VERSION 5.7 ;
BUSBITCHARS "[]" ;
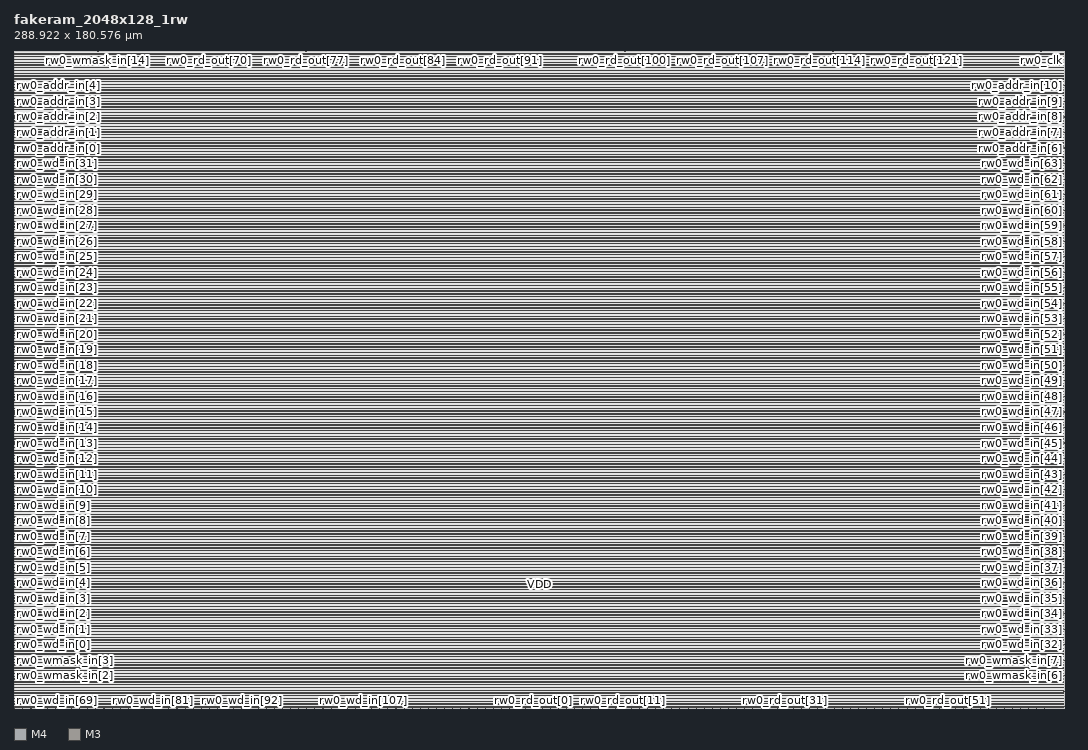
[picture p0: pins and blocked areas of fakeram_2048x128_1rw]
MACRO fakeram_2048x128_1rw
  FOREIGN fakeram_2048x128_1rw 0 0 ;
  SYMMETRY X Y R90 ;
  SIZE 288.922 BY 180.576 ;
  CLASS BLOCK ;
  PIN rw0_wmask_in[0]
    DIRECTION INPUT ;
    USE SIGNAL ;
    SHAPE ABUTMENT ;
    PORT
      LAYER M4 ;
      RECT 0.000 0.276 0.072 0.300 ;
    END
  END rw0_wmask_in[0]
  PIN rw0_wmask_in[1]
    DIRECTION INPUT ;
    USE SIGNAL ;
    SHAPE ABUTMENT ;
    PORT
      LAYER M4 ;
      RECT 0.000 4.548 0.072 4.572 ;
    END
  END rw0_wmask_in[1]
  PIN rw0_wmask_in[2]
    DIRECTION INPUT ;
    USE SIGNAL ;
    SHAPE ABUTMENT ;
    PORT
      LAYER M4 ;
      RECT 0.000 8.820 0.072 8.844 ;
    END
  END rw0_wmask_in[2]
  PIN rw0_wmask_in[3]
    DIRECTION INPUT ;
    USE SIGNAL ;
    SHAPE ABUTMENT ;
    PORT
      LAYER M4 ;
      RECT 0.000 13.092 0.072 13.116 ;
    END
  END rw0_wmask_in[3]
  PIN rw0_wmask_in[4]
    DIRECTION INPUT ;
    USE SIGNAL ;
    SHAPE ABUTMENT ;
    PORT
      LAYER M4 ;
      RECT 288.850 0.276 288.922 0.300 ;
    END
  END rw0_wmask_in[4]
  PIN rw0_wmask_in[5]
    DIRECTION INPUT ;
    USE SIGNAL ;
    SHAPE ABUTMENT ;
    PORT
      LAYER M4 ;
      RECT 288.850 4.548 288.922 4.572 ;
    END
  END rw0_wmask_in[5]
  PIN rw0_wmask_in[6]
    DIRECTION INPUT ;
    USE SIGNAL ;
    SHAPE ABUTMENT ;
    PORT
      LAYER M4 ;
      RECT 288.850 8.820 288.922 8.844 ;
    END
  END rw0_wmask_in[6]
  PIN rw0_wmask_in[7]
    DIRECTION INPUT ;
    USE SIGNAL ;
    SHAPE ABUTMENT ;
    PORT
      LAYER M4 ;
      RECT 288.850 13.092 288.922 13.116 ;
    END
  END rw0_wmask_in[7]
  PIN rw0_wmask_in[8]
    DIRECTION INPUT ;
    USE SIGNAL ;
    SHAPE ABUTMENT ;
    PORT
      LAYER M3 ;
      RECT 0.207 180.522 0.225 180.576 ;
    END
  END rw0_wmask_in[8]
  PIN rw0_wmask_in[9]
    DIRECTION INPUT ;
    USE SIGNAL ;
    SHAPE ABUTMENT ;
    PORT
      LAYER M3 ;
      RECT 4.023 180.522 4.041 180.576 ;
    END
  END rw0_wmask_in[9]
  PIN rw0_wmask_in[10]
    DIRECTION INPUT ;
    USE SIGNAL ;
    SHAPE ABUTMENT ;
    PORT
      LAYER M3 ;
      RECT 7.839 180.522 7.857 180.576 ;
    END
  END rw0_wmask_in[10]
  PIN rw0_wmask_in[11]
    DIRECTION INPUT ;
    USE SIGNAL ;
    SHAPE ABUTMENT ;
    PORT
      LAYER M3 ;
      RECT 11.655 180.522 11.673 180.576 ;
    END
  END rw0_wmask_in[11]
  PIN rw0_wmask_in[12]
    DIRECTION INPUT ;
    USE SIGNAL ;
    SHAPE ABUTMENT ;
    PORT
      LAYER M3 ;
      RECT 15.471 180.522 15.489 180.576 ;
    END
  END rw0_wmask_in[12]
  PIN rw0_wmask_in[13]
    DIRECTION INPUT ;
    USE SIGNAL ;
    SHAPE ABUTMENT ;
    PORT
      LAYER M3 ;
      RECT 19.287 180.522 19.305 180.576 ;
    END
  END rw0_wmask_in[13]
  PIN rw0_wmask_in[14]
    DIRECTION INPUT ;
    USE SIGNAL ;
    SHAPE ABUTMENT ;
    PORT
      LAYER M3 ;
      RECT 23.103 180.522 23.121 180.576 ;
    END
  END rw0_wmask_in[14]
  PIN rw0_wmask_in[15]
    DIRECTION INPUT ;
    USE SIGNAL ;
    SHAPE ABUTMENT ;
    PORT
      LAYER M3 ;
      RECT 26.919 180.522 26.937 180.576 ;
    END
  END rw0_wmask_in[15]
  PIN rw0_wd_in[0]
    DIRECTION INPUT ;
    USE SIGNAL ;
    SHAPE ABUTMENT ;
    PORT
      LAYER M4 ;
      RECT 0.000 17.364 0.072 17.388 ;
    END
  END rw0_wd_in[0]
  PIN rw0_wd_in[1]
    DIRECTION INPUT ;
    USE SIGNAL ;
    SHAPE ABUTMENT ;
    PORT
      LAYER M4 ;
      RECT 0.000 21.636 0.072 21.660 ;
    END
  END rw0_wd_in[1]
  PIN rw0_wd_in[2]
    DIRECTION INPUT ;
    USE SIGNAL ;
    SHAPE ABUTMENT ;
    PORT
      LAYER M4 ;
      RECT 0.000 25.908 0.072 25.932 ;
    END
  END rw0_wd_in[2]
  PIN rw0_wd_in[3]
    DIRECTION INPUT ;
    USE SIGNAL ;
    SHAPE ABUTMENT ;
    PORT
      LAYER M4 ;
      RECT 0.000 30.180 0.072 30.204 ;
    END
  END rw0_wd_in[3]
  PIN rw0_wd_in[4]
    DIRECTION INPUT ;
    USE SIGNAL ;
    SHAPE ABUTMENT ;
    PORT
      LAYER M4 ;
      RECT 0.000 34.452 0.072 34.476 ;
    END
  END rw0_wd_in[4]
  PIN rw0_wd_in[5]
    DIRECTION INPUT ;
    USE SIGNAL ;
    SHAPE ABUTMENT ;
    PORT
      LAYER M4 ;
      RECT 0.000 38.724 0.072 38.748 ;
    END
  END rw0_wd_in[5]
  PIN rw0_wd_in[6]
    DIRECTION INPUT ;
    USE SIGNAL ;
    SHAPE ABUTMENT ;
    PORT
      LAYER M4 ;
      RECT 0.000 42.996 0.072 43.020 ;
    END
  END rw0_wd_in[6]
  PIN rw0_wd_in[7]
    DIRECTION INPUT ;
    USE SIGNAL ;
    SHAPE ABUTMENT ;
    PORT
      LAYER M4 ;
      RECT 0.000 47.268 0.072 47.292 ;
    END
  END rw0_wd_in[7]
  PIN rw0_wd_in[8]
    DIRECTION INPUT ;
    USE SIGNAL ;
    SHAPE ABUTMENT ;
    PORT
      LAYER M4 ;
      RECT 0.000 51.540 0.072 51.564 ;
    END
  END rw0_wd_in[8]
  PIN rw0_wd_in[9]
    DIRECTION INPUT ;
    USE SIGNAL ;
    SHAPE ABUTMENT ;
    PORT
      LAYER M4 ;
      RECT 0.000 55.812 0.072 55.836 ;
    END
  END rw0_wd_in[9]
  PIN rw0_wd_in[10]
    DIRECTION INPUT ;
    USE SIGNAL ;
    SHAPE ABUTMENT ;
    PORT
      LAYER M4 ;
      RECT 0.000 60.084 0.072 60.108 ;
    END
  END rw0_wd_in[10]
  PIN rw0_wd_in[11]
    DIRECTION INPUT ;
    USE SIGNAL ;
    SHAPE ABUTMENT ;
    PORT
      LAYER M4 ;
      RECT 0.000 64.356 0.072 64.380 ;
    END
  END rw0_wd_in[11]
  PIN rw0_wd_in[12]
    DIRECTION INPUT ;
    USE SIGNAL ;
    SHAPE ABUTMENT ;
    PORT
      LAYER M4 ;
      RECT 0.000 68.628 0.072 68.652 ;
    END
  END rw0_wd_in[12]
  PIN rw0_wd_in[13]
    DIRECTION INPUT ;
    USE SIGNAL ;
    SHAPE ABUTMENT ;
    PORT
      LAYER M4 ;
      RECT 0.000 72.900 0.072 72.924 ;
    END
  END rw0_wd_in[13]
  PIN rw0_wd_in[14]
    DIRECTION INPUT ;
    USE SIGNAL ;
    SHAPE ABUTMENT ;
    PORT
      LAYER M4 ;
      RECT 0.000 77.172 0.072 77.196 ;
    END
  END rw0_wd_in[14]
  PIN rw0_wd_in[15]
    DIRECTION INPUT ;
    USE SIGNAL ;
    SHAPE ABUTMENT ;
    PORT
      LAYER M4 ;
      RECT 0.000 81.444 0.072 81.468 ;
    END
  END rw0_wd_in[15]
  PIN rw0_wd_in[16]
    DIRECTION INPUT ;
    USE SIGNAL ;
    SHAPE ABUTMENT ;
    PORT
      LAYER M4 ;
      RECT 0.000 85.716 0.072 85.740 ;
    END
  END rw0_wd_in[16]
  PIN rw0_wd_in[17]
    DIRECTION INPUT ;
    USE SIGNAL ;
    SHAPE ABUTMENT ;
    PORT
      LAYER M4 ;
      RECT 0.000 89.988 0.072 90.012 ;
    END
  END rw0_wd_in[17]
  PIN rw0_wd_in[18]
    DIRECTION INPUT ;
    USE SIGNAL ;
    SHAPE ABUTMENT ;
    PORT
      LAYER M4 ;
      RECT 0.000 94.260 0.072 94.284 ;
    END
  END rw0_wd_in[18]
  PIN rw0_wd_in[19]
    DIRECTION INPUT ;
    USE SIGNAL ;
    SHAPE ABUTMENT ;
    PORT
      LAYER M4 ;
      RECT 0.000 98.532 0.072 98.556 ;
    END
  END rw0_wd_in[19]
  PIN rw0_wd_in[20]
    DIRECTION INPUT ;
    USE SIGNAL ;
    SHAPE ABUTMENT ;
    PORT
      LAYER M4 ;
      RECT 0.000 102.804 0.072 102.828 ;
    END
  END rw0_wd_in[20]
  PIN rw0_wd_in[21]
    DIRECTION INPUT ;
    USE SIGNAL ;
    SHAPE ABUTMENT ;
    PORT
      LAYER M4 ;
      RECT 0.000 107.076 0.072 107.100 ;
    END
  END rw0_wd_in[21]
  PIN rw0_wd_in[22]
    DIRECTION INPUT ;
    USE SIGNAL ;
    SHAPE ABUTMENT ;
    PORT
      LAYER M4 ;
      RECT 0.000 111.348 0.072 111.372 ;
    END
  END rw0_wd_in[22]
  PIN rw0_wd_in[23]
    DIRECTION INPUT ;
    USE SIGNAL ;
    SHAPE ABUTMENT ;
    PORT
      LAYER M4 ;
      RECT 0.000 115.620 0.072 115.644 ;
    END
  END rw0_wd_in[23]
  PIN rw0_wd_in[24]
    DIRECTION INPUT ;
    USE SIGNAL ;
    SHAPE ABUTMENT ;
    PORT
      LAYER M4 ;
      RECT 0.000 119.892 0.072 119.916 ;
    END
  END rw0_wd_in[24]
  PIN rw0_wd_in[25]
    DIRECTION INPUT ;
    USE SIGNAL ;
    SHAPE ABUTMENT ;
    PORT
      LAYER M4 ;
      RECT 0.000 124.164 0.072 124.188 ;
    END
  END rw0_wd_in[25]
  PIN rw0_wd_in[26]
    DIRECTION INPUT ;
    USE SIGNAL ;
    SHAPE ABUTMENT ;
    PORT
      LAYER M4 ;
      RECT 0.000 128.436 0.072 128.460 ;
    END
  END rw0_wd_in[26]
  PIN rw0_wd_in[27]
    DIRECTION INPUT ;
    USE SIGNAL ;
    SHAPE ABUTMENT ;
    PORT
      LAYER M4 ;
      RECT 0.000 132.708 0.072 132.732 ;
    END
  END rw0_wd_in[27]
  PIN rw0_wd_in[28]
    DIRECTION INPUT ;
    USE SIGNAL ;
    SHAPE ABUTMENT ;
    PORT
      LAYER M4 ;
      RECT 0.000 136.980 0.072 137.004 ;
    END
  END rw0_wd_in[28]
  PIN rw0_wd_in[29]
    DIRECTION INPUT ;
    USE SIGNAL ;
    SHAPE ABUTMENT ;
    PORT
      LAYER M4 ;
      RECT 0.000 141.252 0.072 141.276 ;
    END
  END rw0_wd_in[29]
  PIN rw0_wd_in[30]
    DIRECTION INPUT ;
    USE SIGNAL ;
    SHAPE ABUTMENT ;
    PORT
      LAYER M4 ;
      RECT 0.000 145.524 0.072 145.548 ;
    END
  END rw0_wd_in[30]
  PIN rw0_wd_in[31]
    DIRECTION INPUT ;
    USE SIGNAL ;
    SHAPE ABUTMENT ;
    PORT
      LAYER M4 ;
      RECT 0.000 149.796 0.072 149.820 ;
    END
  END rw0_wd_in[31]
  PIN rw0_wd_in[32]
    DIRECTION INPUT ;
    USE SIGNAL ;
    SHAPE ABUTMENT ;
    PORT
      LAYER M4 ;
      RECT 288.850 17.364 288.922 17.388 ;
    END
  END rw0_wd_in[32]
  PIN rw0_wd_in[33]
    DIRECTION INPUT ;
    USE SIGNAL ;
    SHAPE ABUTMENT ;
    PORT
      LAYER M4 ;
      RECT 288.850 21.636 288.922 21.660 ;
    END
  END rw0_wd_in[33]
  PIN rw0_wd_in[34]
    DIRECTION INPUT ;
    USE SIGNAL ;
    SHAPE ABUTMENT ;
    PORT
      LAYER M4 ;
      RECT 288.850 25.908 288.922 25.932 ;
    END
  END rw0_wd_in[34]
  PIN rw0_wd_in[35]
    DIRECTION INPUT ;
    USE SIGNAL ;
    SHAPE ABUTMENT ;
    PORT
      LAYER M4 ;
      RECT 288.850 30.180 288.922 30.204 ;
    END
  END rw0_wd_in[35]
  PIN rw0_wd_in[36]
    DIRECTION INPUT ;
    USE SIGNAL ;
    SHAPE ABUTMENT ;
    PORT
      LAYER M4 ;
      RECT 288.850 34.452 288.922 34.476 ;
    END
  END rw0_wd_in[36]
  PIN rw0_wd_in[37]
    DIRECTION INPUT ;
    USE SIGNAL ;
    SHAPE ABUTMENT ;
    PORT
      LAYER M4 ;
      RECT 288.850 38.724 288.922 38.748 ;
    END
  END rw0_wd_in[37]
  PIN rw0_wd_in[38]
    DIRECTION INPUT ;
    USE SIGNAL ;
    SHAPE ABUTMENT ;
    PORT
      LAYER M4 ;
      RECT 288.850 42.996 288.922 43.020 ;
    END
  END rw0_wd_in[38]
  PIN rw0_wd_in[39]
    DIRECTION INPUT ;
    USE SIGNAL ;
    SHAPE ABUTMENT ;
    PORT
      LAYER M4 ;
      RECT 288.850 47.268 288.922 47.292 ;
    END
  END rw0_wd_in[39]
  PIN rw0_wd_in[40]
    DIRECTION INPUT ;
    USE SIGNAL ;
    SHAPE ABUTMENT ;
    PORT
      LAYER M4 ;
      RECT 288.850 51.540 288.922 51.564 ;
    END
  END rw0_wd_in[40]
  PIN rw0_wd_in[41]
    DIRECTION INPUT ;
    USE SIGNAL ;
    SHAPE ABUTMENT ;
    PORT
      LAYER M4 ;
      RECT 288.850 55.812 288.922 55.836 ;
    END
  END rw0_wd_in[41]
  PIN rw0_wd_in[42]
    DIRECTION INPUT ;
    USE SIGNAL ;
    SHAPE ABUTMENT ;
    PORT
      LAYER M4 ;
      RECT 288.850 60.084 288.922 60.108 ;
    END
  END rw0_wd_in[42]
  PIN rw0_wd_in[43]
    DIRECTION INPUT ;
    USE SIGNAL ;
    SHAPE ABUTMENT ;
    PORT
      LAYER M4 ;
      RECT 288.850 64.356 288.922 64.380 ;
    END
  END rw0_wd_in[43]
  PIN rw0_wd_in[44]
    DIRECTION INPUT ;
    USE SIGNAL ;
    SHAPE ABUTMENT ;
    PORT
      LAYER M4 ;
      RECT 288.850 68.628 288.922 68.652 ;
    END
  END rw0_wd_in[44]
  PIN rw0_wd_in[45]
    DIRECTION INPUT ;
    USE SIGNAL ;
    SHAPE ABUTMENT ;
    PORT
      LAYER M4 ;
      RECT 288.850 72.900 288.922 72.924 ;
    END
  END rw0_wd_in[45]
  PIN rw0_wd_in[46]
    DIRECTION INPUT ;
    USE SIGNAL ;
    SHAPE ABUTMENT ;
    PORT
      LAYER M4 ;
      RECT 288.850 77.172 288.922 77.196 ;
    END
  END rw0_wd_in[46]
  PIN rw0_wd_in[47]
    DIRECTION INPUT ;
    USE SIGNAL ;
    SHAPE ABUTMENT ;
    PORT
      LAYER M4 ;
      RECT 288.850 81.444 288.922 81.468 ;
    END
  END rw0_wd_in[47]
  PIN rw0_wd_in[48]
    DIRECTION INPUT ;
    USE SIGNAL ;
    SHAPE ABUTMENT ;
    PORT
      LAYER M4 ;
      RECT 288.850 85.716 288.922 85.740 ;
    END
  END rw0_wd_in[48]
  PIN rw0_wd_in[49]
    DIRECTION INPUT ;
    USE SIGNAL ;
    SHAPE ABUTMENT ;
    PORT
      LAYER M4 ;
      RECT 288.850 89.988 288.922 90.012 ;
    END
  END rw0_wd_in[49]
  PIN rw0_wd_in[50]
    DIRECTION INPUT ;
    USE SIGNAL ;
    SHAPE ABUTMENT ;
    PORT
      LAYER M4 ;
      RECT 288.850 94.260 288.922 94.284 ;
    END
  END rw0_wd_in[50]
  PIN rw0_wd_in[51]
    DIRECTION INPUT ;
    USE SIGNAL ;
    SHAPE ABUTMENT ;
    PORT
      LAYER M4 ;
      RECT 288.850 98.532 288.922 98.556 ;
    END
  END rw0_wd_in[51]
  PIN rw0_wd_in[52]
    DIRECTION INPUT ;
    USE SIGNAL ;
    SHAPE ABUTMENT ;
    PORT
      LAYER M4 ;
      RECT 288.850 102.804 288.922 102.828 ;
    END
  END rw0_wd_in[52]
  PIN rw0_wd_in[53]
    DIRECTION INPUT ;
    USE SIGNAL ;
    SHAPE ABUTMENT ;
    PORT
      LAYER M4 ;
      RECT 288.850 107.076 288.922 107.100 ;
    END
  END rw0_wd_in[53]
  PIN rw0_wd_in[54]
    DIRECTION INPUT ;
    USE SIGNAL ;
    SHAPE ABUTMENT ;
    PORT
      LAYER M4 ;
      RECT 288.850 111.348 288.922 111.372 ;
    END
  END rw0_wd_in[54]
  PIN rw0_wd_in[55]
    DIRECTION INPUT ;
    USE SIGNAL ;
    SHAPE ABUTMENT ;
    PORT
      LAYER M4 ;
      RECT 288.850 115.620 288.922 115.644 ;
    END
  END rw0_wd_in[55]
  PIN rw0_wd_in[56]
    DIRECTION INPUT ;
    USE SIGNAL ;
    SHAPE ABUTMENT ;
    PORT
      LAYER M4 ;
      RECT 288.850 119.892 288.922 119.916 ;
    END
  END rw0_wd_in[56]
  PIN rw0_wd_in[57]
    DIRECTION INPUT ;
    USE SIGNAL ;
    SHAPE ABUTMENT ;
    PORT
      LAYER M4 ;
      RECT 288.850 124.164 288.922 124.188 ;
    END
  END rw0_wd_in[57]
  PIN rw0_wd_in[58]
    DIRECTION INPUT ;
    USE SIGNAL ;
    SHAPE ABUTMENT ;
    PORT
      LAYER M4 ;
      RECT 288.850 128.436 288.922 128.460 ;
    END
  END rw0_wd_in[58]
  PIN rw0_wd_in[59]
    DIRECTION INPUT ;
    USE SIGNAL ;
    SHAPE ABUTMENT ;
    PORT
      LAYER M4 ;
      RECT 288.850 132.708 288.922 132.732 ;
    END
  END rw0_wd_in[59]
  PIN rw0_wd_in[60]
    DIRECTION INPUT ;
    USE SIGNAL ;
    SHAPE ABUTMENT ;
    PORT
      LAYER M4 ;
      RECT 288.850 136.980 288.922 137.004 ;
    END
  END rw0_wd_in[60]
  PIN rw0_wd_in[61]
    DIRECTION INPUT ;
    USE SIGNAL ;
    SHAPE ABUTMENT ;
    PORT
      LAYER M4 ;
      RECT 288.850 141.252 288.922 141.276 ;
    END
  END rw0_wd_in[61]
  PIN rw0_wd_in[62]
    DIRECTION INPUT ;
    USE SIGNAL ;
    SHAPE ABUTMENT ;
    PORT
      LAYER M4 ;
      RECT 288.850 145.524 288.922 145.548 ;
    END
  END rw0_wd_in[62]
  PIN rw0_wd_in[63]
    DIRECTION INPUT ;
    USE SIGNAL ;
    SHAPE ABUTMENT ;
    PORT
      LAYER M4 ;
      RECT 288.850 149.796 288.922 149.820 ;
    END
  END rw0_wd_in[63]
  PIN rw0_wd_in[64]
    DIRECTION INPUT ;
    USE SIGNAL ;
    SHAPE ABUTMENT ;
    PORT
      LAYER M3 ;
      RECT 0.207 0.000 0.225 0.054 ;
    END
  END rw0_wd_in[64]
  PIN rw0_wd_in[65]
    DIRECTION INPUT ;
    USE SIGNAL ;
    SHAPE ABUTMENT ;
    PORT
      LAYER M3 ;
      RECT 2.439 0.000 2.457 0.054 ;
    END
  END rw0_wd_in[65]
  PIN rw0_wd_in[66]
    DIRECTION INPUT ;
    USE SIGNAL ;
    SHAPE ABUTMENT ;
    PORT
      LAYER M3 ;
      RECT 4.671 0.000 4.689 0.054 ;
    END
  END rw0_wd_in[66]
  PIN rw0_wd_in[67]
    DIRECTION INPUT ;
    USE SIGNAL ;
    SHAPE ABUTMENT ;
    PORT
      LAYER M3 ;
      RECT 6.903 0.000 6.921 0.054 ;
    END
  END rw0_wd_in[67]
  PIN rw0_wd_in[68]
    DIRECTION INPUT ;
    USE SIGNAL ;
    SHAPE ABUTMENT ;
    PORT
      LAYER M3 ;
      RECT 9.135 0.000 9.153 0.054 ;
    END
  END rw0_wd_in[68]
  PIN rw0_wd_in[69]
    DIRECTION INPUT ;
    USE SIGNAL ;
    SHAPE ABUTMENT ;
    PORT
      LAYER M3 ;
      RECT 11.367 0.000 11.385 0.054 ;
    END
  END rw0_wd_in[69]
  PIN rw0_wd_in[70]
    DIRECTION INPUT ;
    USE SIGNAL ;
    SHAPE ABUTMENT ;
    PORT
      LAYER M3 ;
      RECT 13.599 0.000 13.617 0.054 ;
    END
  END rw0_wd_in[70]
  PIN rw0_wd_in[71]
    DIRECTION INPUT ;
    USE SIGNAL ;
    SHAPE ABUTMENT ;
    PORT
      LAYER M3 ;
      RECT 15.831 0.000 15.849 0.054 ;
    END
  END rw0_wd_in[71]
  PIN rw0_wd_in[72]
    DIRECTION INPUT ;
    USE SIGNAL ;
    SHAPE ABUTMENT ;
    PORT
      LAYER M3 ;
      RECT 18.063 0.000 18.081 0.054 ;
    END
  END rw0_wd_in[72]
  PIN rw0_wd_in[73]
    DIRECTION INPUT ;
    USE SIGNAL ;
    SHAPE ABUTMENT ;
    PORT
      LAYER M3 ;
      RECT 20.295 0.000 20.313 0.054 ;
    END
  END rw0_wd_in[73]
  PIN rw0_wd_in[74]
    DIRECTION INPUT ;
    USE SIGNAL ;
    SHAPE ABUTMENT ;
    PORT
      LAYER M3 ;
      RECT 22.527 0.000 22.545 0.054 ;
    END
  END rw0_wd_in[74]
  PIN rw0_wd_in[75]
    DIRECTION INPUT ;
    USE SIGNAL ;
    SHAPE ABUTMENT ;
    PORT
      LAYER M3 ;
      RECT 24.759 0.000 24.777 0.054 ;
    END
  END rw0_wd_in[75]
  PIN rw0_wd_in[76]
    DIRECTION INPUT ;
    USE SIGNAL ;
    SHAPE ABUTMENT ;
    PORT
      LAYER M3 ;
      RECT 26.991 0.000 27.009 0.054 ;
    END
  END rw0_wd_in[76]
  PIN rw0_wd_in[77]
    DIRECTION INPUT ;
    USE SIGNAL ;
    SHAPE ABUTMENT ;
    PORT
      LAYER M3 ;
      RECT 29.223 0.000 29.241 0.054 ;
    END
  END rw0_wd_in[77]
  PIN rw0_wd_in[78]
    DIRECTION INPUT ;
    USE SIGNAL ;
    SHAPE ABUTMENT ;
    PORT
      LAYER M3 ;
      RECT 31.455 0.000 31.473 0.054 ;
    END
  END rw0_wd_in[78]
  PIN rw0_wd_in[79]
    DIRECTION INPUT ;
    USE SIGNAL ;
    SHAPE ABUTMENT ;
    PORT
      LAYER M3 ;
      RECT 33.687 0.000 33.705 0.054 ;
    END
  END rw0_wd_in[79]
  PIN rw0_wd_in[80]
    DIRECTION INPUT ;
    USE SIGNAL ;
    SHAPE ABUTMENT ;
    PORT
      LAYER M3 ;
      RECT 35.919 0.000 35.937 0.054 ;
    END
  END rw0_wd_in[80]
  PIN rw0_wd_in[81]
    DIRECTION INPUT ;
    USE SIGNAL ;
    SHAPE ABUTMENT ;
    PORT
      LAYER M3 ;
      RECT 38.151 0.000 38.169 0.054 ;
    END
  END rw0_wd_in[81]
  PIN rw0_wd_in[82]
    DIRECTION INPUT ;
    USE SIGNAL ;
    SHAPE ABUTMENT ;
    PORT
      LAYER M3 ;
      RECT 40.383 0.000 40.401 0.054 ;
    END
  END rw0_wd_in[82]
  PIN rw0_wd_in[83]
    DIRECTION INPUT ;
    USE SIGNAL ;
    SHAPE ABUTMENT ;
    PORT
      LAYER M3 ;
      RECT 42.615 0.000 42.633 0.054 ;
    END
  END rw0_wd_in[83]
  PIN rw0_wd_in[84]
    DIRECTION INPUT ;
    USE SIGNAL ;
    SHAPE ABUTMENT ;
    PORT
      LAYER M3 ;
      RECT 44.847 0.000 44.865 0.054 ;
    END
  END rw0_wd_in[84]
  PIN rw0_wd_in[85]
    DIRECTION INPUT ;
    USE SIGNAL ;
    SHAPE ABUTMENT ;
    PORT
      LAYER M3 ;
      RECT 47.079 0.000 47.097 0.054 ;
    END
  END rw0_wd_in[85]
  PIN rw0_wd_in[86]
    DIRECTION INPUT ;
    USE SIGNAL ;
    SHAPE ABUTMENT ;
    PORT
      LAYER M3 ;
      RECT 49.311 0.000 49.329 0.054 ;
    END
  END rw0_wd_in[86]
  PIN rw0_wd_in[87]
    DIRECTION INPUT ;
    USE SIGNAL ;
    SHAPE ABUTMENT ;
    PORT
      LAYER M3 ;
      RECT 51.543 0.000 51.561 0.054 ;
    END
  END rw0_wd_in[87]
  PIN rw0_wd_in[88]
    DIRECTION INPUT ;
    USE SIGNAL ;
    SHAPE ABUTMENT ;
    PORT
      LAYER M3 ;
      RECT 53.775 0.000 53.793 0.054 ;
    END
  END rw0_wd_in[88]
  PIN rw0_wd_in[89]
    DIRECTION INPUT ;
    USE SIGNAL ;
    SHAPE ABUTMENT ;
    PORT
      LAYER M3 ;
      RECT 56.007 0.000 56.025 0.054 ;
    END
  END rw0_wd_in[89]
  PIN rw0_wd_in[90]
    DIRECTION INPUT ;
    USE SIGNAL ;
    SHAPE ABUTMENT ;
    PORT
      LAYER M3 ;
      RECT 58.239 0.000 58.257 0.054 ;
    END
  END rw0_wd_in[90]
  PIN rw0_wd_in[91]
    DIRECTION INPUT ;
    USE SIGNAL ;
    SHAPE ABUTMENT ;
    PORT
      LAYER M3 ;
      RECT 60.471 0.000 60.489 0.054 ;
    END
  END rw0_wd_in[91]
  PIN rw0_wd_in[92]
    DIRECTION INPUT ;
    USE SIGNAL ;
    SHAPE ABUTMENT ;
    PORT
      LAYER M3 ;
      RECT 62.703 0.000 62.721 0.054 ;
    END
  END rw0_wd_in[92]
  PIN rw0_wd_in[93]
    DIRECTION INPUT ;
    USE SIGNAL ;
    SHAPE ABUTMENT ;
    PORT
      LAYER M3 ;
      RECT 64.935 0.000 64.953 0.054 ;
    END
  END rw0_wd_in[93]
  PIN rw0_wd_in[94]
    DIRECTION INPUT ;
    USE SIGNAL ;
    SHAPE ABUTMENT ;
    PORT
      LAYER M3 ;
      RECT 67.167 0.000 67.185 0.054 ;
    END
  END rw0_wd_in[94]
  PIN rw0_wd_in[95]
    DIRECTION INPUT ;
    USE SIGNAL ;
    SHAPE ABUTMENT ;
    PORT
      LAYER M3 ;
      RECT 69.399 0.000 69.417 0.054 ;
    END
  END rw0_wd_in[95]
  PIN rw0_wd_in[96]
    DIRECTION INPUT ;
    USE SIGNAL ;
    SHAPE ABUTMENT ;
    PORT
      LAYER M3 ;
      RECT 71.631 0.000 71.649 0.054 ;
    END
  END rw0_wd_in[96]
  PIN rw0_wd_in[97]
    DIRECTION INPUT ;
    USE SIGNAL ;
    SHAPE ABUTMENT ;
    PORT
      LAYER M3 ;
      RECT 73.863 0.000 73.881 0.054 ;
    END
  END rw0_wd_in[97]
  PIN rw0_wd_in[98]
    DIRECTION INPUT ;
    USE SIGNAL ;
    SHAPE ABUTMENT ;
    PORT
      LAYER M3 ;
      RECT 76.095 0.000 76.113 0.054 ;
    END
  END rw0_wd_in[98]
  PIN rw0_wd_in[99]
    DIRECTION INPUT ;
    USE SIGNAL ;
    SHAPE ABUTMENT ;
    PORT
      LAYER M3 ;
      RECT 78.327 0.000 78.345 0.054 ;
    END
  END rw0_wd_in[99]
  PIN rw0_wd_in[100]
    DIRECTION INPUT ;
    USE SIGNAL ;
    SHAPE ABUTMENT ;
    PORT
      LAYER M3 ;
      RECT 80.559 0.000 80.577 0.054 ;
    END
  END rw0_wd_in[100]
  PIN rw0_wd_in[101]
    DIRECTION INPUT ;
    USE SIGNAL ;
    SHAPE ABUTMENT ;
    PORT
      LAYER M3 ;
      RECT 82.791 0.000 82.809 0.054 ;
    END
  END rw0_wd_in[101]
  PIN rw0_wd_in[102]
    DIRECTION INPUT ;
    USE SIGNAL ;
    SHAPE ABUTMENT ;
    PORT
      LAYER M3 ;
      RECT 85.023 0.000 85.041 0.054 ;
    END
  END rw0_wd_in[102]
  PIN rw0_wd_in[103]
    DIRECTION INPUT ;
    USE SIGNAL ;
    SHAPE ABUTMENT ;
    PORT
      LAYER M3 ;
      RECT 87.255 0.000 87.273 0.054 ;
    END
  END rw0_wd_in[103]
  PIN rw0_wd_in[104]
    DIRECTION INPUT ;
    USE SIGNAL ;
    SHAPE ABUTMENT ;
    PORT
      LAYER M3 ;
      RECT 89.487 0.000 89.505 0.054 ;
    END
  END rw0_wd_in[104]
  PIN rw0_wd_in[105]
    DIRECTION INPUT ;
    USE SIGNAL ;
    SHAPE ABUTMENT ;
    PORT
      LAYER M3 ;
      RECT 91.719 0.000 91.737 0.054 ;
    END
  END rw0_wd_in[105]
  PIN rw0_wd_in[106]
    DIRECTION INPUT ;
    USE SIGNAL ;
    SHAPE ABUTMENT ;
    PORT
      LAYER M3 ;
      RECT 93.951 0.000 93.969 0.054 ;
    END
  END rw0_wd_in[106]
  PIN rw0_wd_in[107]
    DIRECTION INPUT ;
    USE SIGNAL ;
    SHAPE ABUTMENT ;
    PORT
      LAYER M3 ;
      RECT 96.183 0.000 96.201 0.054 ;
    END
  END rw0_wd_in[107]
  PIN rw0_wd_in[108]
    DIRECTION INPUT ;
    USE SIGNAL ;
    SHAPE ABUTMENT ;
    PORT
      LAYER M3 ;
      RECT 98.415 0.000 98.433 0.054 ;
    END
  END rw0_wd_in[108]
  PIN rw0_wd_in[109]
    DIRECTION INPUT ;
    USE SIGNAL ;
    SHAPE ABUTMENT ;
    PORT
      LAYER M3 ;
      RECT 100.647 0.000 100.665 0.054 ;
    END
  END rw0_wd_in[109]
  PIN rw0_wd_in[110]
    DIRECTION INPUT ;
    USE SIGNAL ;
    SHAPE ABUTMENT ;
    PORT
      LAYER M3 ;
      RECT 102.879 0.000 102.897 0.054 ;
    END
  END rw0_wd_in[110]
  PIN rw0_wd_in[111]
    DIRECTION INPUT ;
    USE SIGNAL ;
    SHAPE ABUTMENT ;
    PORT
      LAYER M3 ;
      RECT 105.111 0.000 105.129 0.054 ;
    END
  END rw0_wd_in[111]
  PIN rw0_wd_in[112]
    DIRECTION INPUT ;
    USE SIGNAL ;
    SHAPE ABUTMENT ;
    PORT
      LAYER M3 ;
      RECT 107.343 0.000 107.361 0.054 ;
    END
  END rw0_wd_in[112]
  PIN rw0_wd_in[113]
    DIRECTION INPUT ;
    USE SIGNAL ;
    SHAPE ABUTMENT ;
    PORT
      LAYER M3 ;
      RECT 109.575 0.000 109.593 0.054 ;
    END
  END rw0_wd_in[113]
  PIN rw0_wd_in[114]
    DIRECTION INPUT ;
    USE SIGNAL ;
    SHAPE ABUTMENT ;
    PORT
      LAYER M3 ;
      RECT 111.807 0.000 111.825 0.054 ;
    END
  END rw0_wd_in[114]
  PIN rw0_wd_in[115]
    DIRECTION INPUT ;
    USE SIGNAL ;
    SHAPE ABUTMENT ;
    PORT
      LAYER M3 ;
      RECT 114.039 0.000 114.057 0.054 ;
    END
  END rw0_wd_in[115]
  PIN rw0_wd_in[116]
    DIRECTION INPUT ;
    USE SIGNAL ;
    SHAPE ABUTMENT ;
    PORT
      LAYER M3 ;
      RECT 116.271 0.000 116.289 0.054 ;
    END
  END rw0_wd_in[116]
  PIN rw0_wd_in[117]
    DIRECTION INPUT ;
    USE SIGNAL ;
    SHAPE ABUTMENT ;
    PORT
      LAYER M3 ;
      RECT 118.503 0.000 118.521 0.054 ;
    END
  END rw0_wd_in[117]
  PIN rw0_wd_in[118]
    DIRECTION INPUT ;
    USE SIGNAL ;
    SHAPE ABUTMENT ;
    PORT
      LAYER M3 ;
      RECT 120.735 0.000 120.753 0.054 ;
    END
  END rw0_wd_in[118]
  PIN rw0_wd_in[119]
    DIRECTION INPUT ;
    USE SIGNAL ;
    SHAPE ABUTMENT ;
    PORT
      LAYER M3 ;
      RECT 122.967 0.000 122.985 0.054 ;
    END
  END rw0_wd_in[119]
  PIN rw0_wd_in[120]
    DIRECTION INPUT ;
    USE SIGNAL ;
    SHAPE ABUTMENT ;
    PORT
      LAYER M3 ;
      RECT 125.199 0.000 125.217 0.054 ;
    END
  END rw0_wd_in[120]
  PIN rw0_wd_in[121]
    DIRECTION INPUT ;
    USE SIGNAL ;
    SHAPE ABUTMENT ;
    PORT
      LAYER M3 ;
      RECT 127.431 0.000 127.449 0.054 ;
    END
  END rw0_wd_in[121]
  PIN rw0_wd_in[122]
    DIRECTION INPUT ;
    USE SIGNAL ;
    SHAPE ABUTMENT ;
    PORT
      LAYER M3 ;
      RECT 129.663 0.000 129.681 0.054 ;
    END
  END rw0_wd_in[122]
  PIN rw0_wd_in[123]
    DIRECTION INPUT ;
    USE SIGNAL ;
    SHAPE ABUTMENT ;
    PORT
      LAYER M3 ;
      RECT 131.895 0.000 131.913 0.054 ;
    END
  END rw0_wd_in[123]
  PIN rw0_wd_in[124]
    DIRECTION INPUT ;
    USE SIGNAL ;
    SHAPE ABUTMENT ;
    PORT
      LAYER M3 ;
      RECT 134.127 0.000 134.145 0.054 ;
    END
  END rw0_wd_in[124]
  PIN rw0_wd_in[125]
    DIRECTION INPUT ;
    USE SIGNAL ;
    SHAPE ABUTMENT ;
    PORT
      LAYER M3 ;
      RECT 136.359 0.000 136.377 0.054 ;
    END
  END rw0_wd_in[125]
  PIN rw0_wd_in[126]
    DIRECTION INPUT ;
    USE SIGNAL ;
    SHAPE ABUTMENT ;
    PORT
      LAYER M3 ;
      RECT 138.591 0.000 138.609 0.054 ;
    END
  END rw0_wd_in[126]
  PIN rw0_wd_in[127]
    DIRECTION INPUT ;
    USE SIGNAL ;
    SHAPE ABUTMENT ;
    PORT
      LAYER M3 ;
      RECT 140.823 0.000 140.841 0.054 ;
    END
  END rw0_wd_in[127]
  PIN rw0_rd_out[0]
    DIRECTION OUTPUT ;
    USE SIGNAL ;
    SHAPE ABUTMENT ;
    PORT
      LAYER M3 ;
      RECT 143.055 0.000 143.073 0.054 ;
    END
  END rw0_rd_out[0]
  PIN rw0_rd_out[1]
    DIRECTION OUTPUT ;
    USE SIGNAL ;
    SHAPE ABUTMENT ;
    PORT
      LAYER M3 ;
      RECT 145.287 0.000 145.305 0.054 ;
    END
  END rw0_rd_out[1]
  PIN rw0_rd_out[2]
    DIRECTION OUTPUT ;
    USE SIGNAL ;
    SHAPE ABUTMENT ;
    PORT
      LAYER M3 ;
      RECT 147.519 0.000 147.537 0.054 ;
    END
  END rw0_rd_out[2]
  PIN rw0_rd_out[3]
    DIRECTION OUTPUT ;
    USE SIGNAL ;
    SHAPE ABUTMENT ;
    PORT
      LAYER M3 ;
      RECT 149.751 0.000 149.769 0.054 ;
    END
  END rw0_rd_out[3]
  PIN rw0_rd_out[4]
    DIRECTION OUTPUT ;
    USE SIGNAL ;
    SHAPE ABUTMENT ;
    PORT
      LAYER M3 ;
      RECT 151.983 0.000 152.001 0.054 ;
    END
  END rw0_rd_out[4]
  PIN rw0_rd_out[5]
    DIRECTION OUTPUT ;
    USE SIGNAL ;
    SHAPE ABUTMENT ;
    PORT
      LAYER M3 ;
      RECT 154.215 0.000 154.233 0.054 ;
    END
  END rw0_rd_out[5]
  PIN rw0_rd_out[6]
    DIRECTION OUTPUT ;
    USE SIGNAL ;
    SHAPE ABUTMENT ;
    PORT
      LAYER M3 ;
      RECT 156.447 0.000 156.465 0.054 ;
    END
  END rw0_rd_out[6]
  PIN rw0_rd_out[7]
    DIRECTION OUTPUT ;
    USE SIGNAL ;
    SHAPE ABUTMENT ;
    PORT
      LAYER M3 ;
      RECT 158.679 0.000 158.697 0.054 ;
    END
  END rw0_rd_out[7]
  PIN rw0_rd_out[8]
    DIRECTION OUTPUT ;
    USE SIGNAL ;
    SHAPE ABUTMENT ;
    PORT
      LAYER M3 ;
      RECT 160.911 0.000 160.929 0.054 ;
    END
  END rw0_rd_out[8]
  PIN rw0_rd_out[9]
    DIRECTION OUTPUT ;
    USE SIGNAL ;
    SHAPE ABUTMENT ;
    PORT
      LAYER M3 ;
      RECT 163.143 0.000 163.161 0.054 ;
    END
  END rw0_rd_out[9]
  PIN rw0_rd_out[10]
    DIRECTION OUTPUT ;
    USE SIGNAL ;
    SHAPE ABUTMENT ;
    PORT
      LAYER M3 ;
      RECT 165.375 0.000 165.393 0.054 ;
    END
  END rw0_rd_out[10]
  PIN rw0_rd_out[11]
    DIRECTION OUTPUT ;
    USE SIGNAL ;
    SHAPE ABUTMENT ;
    PORT
      LAYER M3 ;
      RECT 167.607 0.000 167.625 0.054 ;
    END
  END rw0_rd_out[11]
  PIN rw0_rd_out[12]
    DIRECTION OUTPUT ;
    USE SIGNAL ;
    SHAPE ABUTMENT ;
    PORT
      LAYER M3 ;
      RECT 169.839 0.000 169.857 0.054 ;
    END
  END rw0_rd_out[12]
  PIN rw0_rd_out[13]
    DIRECTION OUTPUT ;
    USE SIGNAL ;
    SHAPE ABUTMENT ;
    PORT
      LAYER M3 ;
      RECT 172.071 0.000 172.089 0.054 ;
    END
  END rw0_rd_out[13]
  PIN rw0_rd_out[14]
    DIRECTION OUTPUT ;
    USE SIGNAL ;
    SHAPE ABUTMENT ;
    PORT
      LAYER M3 ;
      RECT 174.303 0.000 174.321 0.054 ;
    END
  END rw0_rd_out[14]
  PIN rw0_rd_out[15]
    DIRECTION OUTPUT ;
    USE SIGNAL ;
    SHAPE ABUTMENT ;
    PORT
      LAYER M3 ;
      RECT 176.535 0.000 176.553 0.054 ;
    END
  END rw0_rd_out[15]
  PIN rw0_rd_out[16]
    DIRECTION OUTPUT ;
    USE SIGNAL ;
    SHAPE ABUTMENT ;
    PORT
      LAYER M3 ;
      RECT 178.767 0.000 178.785 0.054 ;
    END
  END rw0_rd_out[16]
  PIN rw0_rd_out[17]
    DIRECTION OUTPUT ;
    USE SIGNAL ;
    SHAPE ABUTMENT ;
    PORT
      LAYER M3 ;
      RECT 180.999 0.000 181.017 0.054 ;
    END
  END rw0_rd_out[17]
  PIN rw0_rd_out[18]
    DIRECTION OUTPUT ;
    USE SIGNAL ;
    SHAPE ABUTMENT ;
    PORT
      LAYER M3 ;
      RECT 183.231 0.000 183.249 0.054 ;
    END
  END rw0_rd_out[18]
  PIN rw0_rd_out[19]
    DIRECTION OUTPUT ;
    USE SIGNAL ;
    SHAPE ABUTMENT ;
    PORT
      LAYER M3 ;
      RECT 185.463 0.000 185.481 0.054 ;
    END
  END rw0_rd_out[19]
  PIN rw0_rd_out[20]
    DIRECTION OUTPUT ;
    USE SIGNAL ;
    SHAPE ABUTMENT ;
    PORT
      LAYER M3 ;
      RECT 187.695 0.000 187.713 0.054 ;
    END
  END rw0_rd_out[20]
  PIN rw0_rd_out[21]
    DIRECTION OUTPUT ;
    USE SIGNAL ;
    SHAPE ABUTMENT ;
    PORT
      LAYER M3 ;
      RECT 189.927 0.000 189.945 0.054 ;
    END
  END rw0_rd_out[21]
  PIN rw0_rd_out[22]
    DIRECTION OUTPUT ;
    USE SIGNAL ;
    SHAPE ABUTMENT ;
    PORT
      LAYER M3 ;
      RECT 192.159 0.000 192.177 0.054 ;
    END
  END rw0_rd_out[22]
  PIN rw0_rd_out[23]
    DIRECTION OUTPUT ;
    USE SIGNAL ;
    SHAPE ABUTMENT ;
    PORT
      LAYER M3 ;
      RECT 194.391 0.000 194.409 0.054 ;
    END
  END rw0_rd_out[23]
  PIN rw0_rd_out[24]
    DIRECTION OUTPUT ;
    USE SIGNAL ;
    SHAPE ABUTMENT ;
    PORT
      LAYER M3 ;
      RECT 196.623 0.000 196.641 0.054 ;
    END
  END rw0_rd_out[24]
  PIN rw0_rd_out[25]
    DIRECTION OUTPUT ;
    USE SIGNAL ;
    SHAPE ABUTMENT ;
    PORT
      LAYER M3 ;
      RECT 198.855 0.000 198.873 0.054 ;
    END
  END rw0_rd_out[25]
  PIN rw0_rd_out[26]
    DIRECTION OUTPUT ;
    USE SIGNAL ;
    SHAPE ABUTMENT ;
    PORT
      LAYER M3 ;
      RECT 201.087 0.000 201.105 0.054 ;
    END
  END rw0_rd_out[26]
  PIN rw0_rd_out[27]
    DIRECTION OUTPUT ;
    USE SIGNAL ;
    SHAPE ABUTMENT ;
    PORT
      LAYER M3 ;
      RECT 203.319 0.000 203.337 0.054 ;
    END
  END rw0_rd_out[27]
  PIN rw0_rd_out[28]
    DIRECTION OUTPUT ;
    USE SIGNAL ;
    SHAPE ABUTMENT ;
    PORT
      LAYER M3 ;
      RECT 205.551 0.000 205.569 0.054 ;
    END
  END rw0_rd_out[28]
  PIN rw0_rd_out[29]
    DIRECTION OUTPUT ;
    USE SIGNAL ;
    SHAPE ABUTMENT ;
    PORT
      LAYER M3 ;
      RECT 207.783 0.000 207.801 0.054 ;
    END
  END rw0_rd_out[29]
  PIN rw0_rd_out[30]
    DIRECTION OUTPUT ;
    USE SIGNAL ;
    SHAPE ABUTMENT ;
    PORT
      LAYER M3 ;
      RECT 210.015 0.000 210.033 0.054 ;
    END
  END rw0_rd_out[30]
  PIN rw0_rd_out[31]
    DIRECTION OUTPUT ;
    USE SIGNAL ;
    SHAPE ABUTMENT ;
    PORT
      LAYER M3 ;
      RECT 212.247 0.000 212.265 0.054 ;
    END
  END rw0_rd_out[31]
  PIN rw0_rd_out[32]
    DIRECTION OUTPUT ;
    USE SIGNAL ;
    SHAPE ABUTMENT ;
    PORT
      LAYER M3 ;
      RECT 214.479 0.000 214.497 0.054 ;
    END
  END rw0_rd_out[32]
  PIN rw0_rd_out[33]
    DIRECTION OUTPUT ;
    USE SIGNAL ;
    SHAPE ABUTMENT ;
    PORT
      LAYER M3 ;
      RECT 216.711 0.000 216.729 0.054 ;
    END
  END rw0_rd_out[33]
  PIN rw0_rd_out[34]
    DIRECTION OUTPUT ;
    USE SIGNAL ;
    SHAPE ABUTMENT ;
    PORT
      LAYER M3 ;
      RECT 218.943 0.000 218.961 0.054 ;
    END
  END rw0_rd_out[34]
  PIN rw0_rd_out[35]
    DIRECTION OUTPUT ;
    USE SIGNAL ;
    SHAPE ABUTMENT ;
    PORT
      LAYER M3 ;
      RECT 221.175 0.000 221.193 0.054 ;
    END
  END rw0_rd_out[35]
  PIN rw0_rd_out[36]
    DIRECTION OUTPUT ;
    USE SIGNAL ;
    SHAPE ABUTMENT ;
    PORT
      LAYER M3 ;
      RECT 223.407 0.000 223.425 0.054 ;
    END
  END rw0_rd_out[36]
  PIN rw0_rd_out[37]
    DIRECTION OUTPUT ;
    USE SIGNAL ;
    SHAPE ABUTMENT ;
    PORT
      LAYER M3 ;
      RECT 225.639 0.000 225.657 0.054 ;
    END
  END rw0_rd_out[37]
  PIN rw0_rd_out[38]
    DIRECTION OUTPUT ;
    USE SIGNAL ;
    SHAPE ABUTMENT ;
    PORT
      LAYER M3 ;
      RECT 227.871 0.000 227.889 0.054 ;
    END
  END rw0_rd_out[38]
  PIN rw0_rd_out[39]
    DIRECTION OUTPUT ;
    USE SIGNAL ;
    SHAPE ABUTMENT ;
    PORT
      LAYER M3 ;
      RECT 230.103 0.000 230.121 0.054 ;
    END
  END rw0_rd_out[39]
  PIN rw0_rd_out[40]
    DIRECTION OUTPUT ;
    USE SIGNAL ;
    SHAPE ABUTMENT ;
    PORT
      LAYER M3 ;
      RECT 232.335 0.000 232.353 0.054 ;
    END
  END rw0_rd_out[40]
  PIN rw0_rd_out[41]
    DIRECTION OUTPUT ;
    USE SIGNAL ;
    SHAPE ABUTMENT ;
    PORT
      LAYER M3 ;
      RECT 234.567 0.000 234.585 0.054 ;
    END
  END rw0_rd_out[41]
  PIN rw0_rd_out[42]
    DIRECTION OUTPUT ;
    USE SIGNAL ;
    SHAPE ABUTMENT ;
    PORT
      LAYER M3 ;
      RECT 236.799 0.000 236.817 0.054 ;
    END
  END rw0_rd_out[42]
  PIN rw0_rd_out[43]
    DIRECTION OUTPUT ;
    USE SIGNAL ;
    SHAPE ABUTMENT ;
    PORT
      LAYER M3 ;
      RECT 239.031 0.000 239.049 0.054 ;
    END
  END rw0_rd_out[43]
  PIN rw0_rd_out[44]
    DIRECTION OUTPUT ;
    USE SIGNAL ;
    SHAPE ABUTMENT ;
    PORT
      LAYER M3 ;
      RECT 241.263 0.000 241.281 0.054 ;
    END
  END rw0_rd_out[44]
  PIN rw0_rd_out[45]
    DIRECTION OUTPUT ;
    USE SIGNAL ;
    SHAPE ABUTMENT ;
    PORT
      LAYER M3 ;
      RECT 243.495 0.000 243.513 0.054 ;
    END
  END rw0_rd_out[45]
  PIN rw0_rd_out[46]
    DIRECTION OUTPUT ;
    USE SIGNAL ;
    SHAPE ABUTMENT ;
    PORT
      LAYER M3 ;
      RECT 245.727 0.000 245.745 0.054 ;
    END
  END rw0_rd_out[46]
  PIN rw0_rd_out[47]
    DIRECTION OUTPUT ;
    USE SIGNAL ;
    SHAPE ABUTMENT ;
    PORT
      LAYER M3 ;
      RECT 247.959 0.000 247.977 0.054 ;
    END
  END rw0_rd_out[47]
  PIN rw0_rd_out[48]
    DIRECTION OUTPUT ;
    USE SIGNAL ;
    SHAPE ABUTMENT ;
    PORT
      LAYER M3 ;
      RECT 250.191 0.000 250.209 0.054 ;
    END
  END rw0_rd_out[48]
  PIN rw0_rd_out[49]
    DIRECTION OUTPUT ;
    USE SIGNAL ;
    SHAPE ABUTMENT ;
    PORT
      LAYER M3 ;
      RECT 252.423 0.000 252.441 0.054 ;
    END
  END rw0_rd_out[49]
  PIN rw0_rd_out[50]
    DIRECTION OUTPUT ;
    USE SIGNAL ;
    SHAPE ABUTMENT ;
    PORT
      LAYER M3 ;
      RECT 254.655 0.000 254.673 0.054 ;
    END
  END rw0_rd_out[50]
  PIN rw0_rd_out[51]
    DIRECTION OUTPUT ;
    USE SIGNAL ;
    SHAPE ABUTMENT ;
    PORT
      LAYER M3 ;
      RECT 256.887 0.000 256.905 0.054 ;
    END
  END rw0_rd_out[51]
  PIN rw0_rd_out[52]
    DIRECTION OUTPUT ;
    USE SIGNAL ;
    SHAPE ABUTMENT ;
    PORT
      LAYER M3 ;
      RECT 259.119 0.000 259.137 0.054 ;
    END
  END rw0_rd_out[52]
  PIN rw0_rd_out[53]
    DIRECTION OUTPUT ;
    USE SIGNAL ;
    SHAPE ABUTMENT ;
    PORT
      LAYER M3 ;
      RECT 261.351 0.000 261.369 0.054 ;
    END
  END rw0_rd_out[53]
  PIN rw0_rd_out[54]
    DIRECTION OUTPUT ;
    USE SIGNAL ;
    SHAPE ABUTMENT ;
    PORT
      LAYER M3 ;
      RECT 263.583 0.000 263.601 0.054 ;
    END
  END rw0_rd_out[54]
  PIN rw0_rd_out[55]
    DIRECTION OUTPUT ;
    USE SIGNAL ;
    SHAPE ABUTMENT ;
    PORT
      LAYER M3 ;
      RECT 265.815 0.000 265.833 0.054 ;
    END
  END rw0_rd_out[55]
  PIN rw0_rd_out[56]
    DIRECTION OUTPUT ;
    USE SIGNAL ;
    SHAPE ABUTMENT ;
    PORT
      LAYER M3 ;
      RECT 268.047 0.000 268.065 0.054 ;
    END
  END rw0_rd_out[56]
  PIN rw0_rd_out[57]
    DIRECTION OUTPUT ;
    USE SIGNAL ;
    SHAPE ABUTMENT ;
    PORT
      LAYER M3 ;
      RECT 270.279 0.000 270.297 0.054 ;
    END
  END rw0_rd_out[57]
  PIN rw0_rd_out[58]
    DIRECTION OUTPUT ;
    USE SIGNAL ;
    SHAPE ABUTMENT ;
    PORT
      LAYER M3 ;
      RECT 272.511 0.000 272.529 0.054 ;
    END
  END rw0_rd_out[58]
  PIN rw0_rd_out[59]
    DIRECTION OUTPUT ;
    USE SIGNAL ;
    SHAPE ABUTMENT ;
    PORT
      LAYER M3 ;
      RECT 274.743 0.000 274.761 0.054 ;
    END
  END rw0_rd_out[59]
  PIN rw0_rd_out[60]
    DIRECTION OUTPUT ;
    USE SIGNAL ;
    SHAPE ABUTMENT ;
    PORT
      LAYER M3 ;
      RECT 276.975 0.000 276.993 0.054 ;
    END
  END rw0_rd_out[60]
  PIN rw0_rd_out[61]
    DIRECTION OUTPUT ;
    USE SIGNAL ;
    SHAPE ABUTMENT ;
    PORT
      LAYER M3 ;
      RECT 279.207 0.000 279.225 0.054 ;
    END
  END rw0_rd_out[61]
  PIN rw0_rd_out[62]
    DIRECTION OUTPUT ;
    USE SIGNAL ;
    SHAPE ABUTMENT ;
    PORT
      LAYER M3 ;
      RECT 281.439 0.000 281.457 0.054 ;
    END
  END rw0_rd_out[62]
  PIN rw0_rd_out[63]
    DIRECTION OUTPUT ;
    USE SIGNAL ;
    SHAPE ABUTMENT ;
    PORT
      LAYER M3 ;
      RECT 283.671 0.000 283.689 0.054 ;
    END
  END rw0_rd_out[63]
  PIN rw0_rd_out[64]
    DIRECTION OUTPUT ;
    USE SIGNAL ;
    SHAPE ABUTMENT ;
    PORT
      LAYER M3 ;
      RECT 30.735 180.522 30.753 180.576 ;
    END
  END rw0_rd_out[64]
  PIN rw0_rd_out[65]
    DIRECTION OUTPUT ;
    USE SIGNAL ;
    SHAPE ABUTMENT ;
    PORT
      LAYER M3 ;
      RECT 34.551 180.522 34.569 180.576 ;
    END
  END rw0_rd_out[65]
  PIN rw0_rd_out[66]
    DIRECTION OUTPUT ;
    USE SIGNAL ;
    SHAPE ABUTMENT ;
    PORT
      LAYER M3 ;
      RECT 38.367 180.522 38.385 180.576 ;
    END
  END rw0_rd_out[66]
  PIN rw0_rd_out[67]
    DIRECTION OUTPUT ;
    USE SIGNAL ;
    SHAPE ABUTMENT ;
    PORT
      LAYER M3 ;
      RECT 42.183 180.522 42.201 180.576 ;
    END
  END rw0_rd_out[67]
  PIN rw0_rd_out[68]
    DIRECTION OUTPUT ;
    USE SIGNAL ;
    SHAPE ABUTMENT ;
    PORT
      LAYER M3 ;
      RECT 45.999 180.522 46.017 180.576 ;
    END
  END rw0_rd_out[68]
  PIN rw0_rd_out[69]
    DIRECTION OUTPUT ;
    USE SIGNAL ;
    SHAPE ABUTMENT ;
    PORT
      LAYER M3 ;
      RECT 49.815 180.522 49.833 180.576 ;
    END
  END rw0_rd_out[69]
  PIN rw0_rd_out[70]
    DIRECTION OUTPUT ;
    USE SIGNAL ;
    SHAPE ABUTMENT ;
    PORT
      LAYER M3 ;
      RECT 53.631 180.522 53.649 180.576 ;
    END
  END rw0_rd_out[70]
  PIN rw0_rd_out[71]
    DIRECTION OUTPUT ;
    USE SIGNAL ;
    SHAPE ABUTMENT ;
    PORT
      LAYER M3 ;
      RECT 57.447 180.522 57.465 180.576 ;
    END
  END rw0_rd_out[71]
  PIN rw0_rd_out[72]
    DIRECTION OUTPUT ;
    USE SIGNAL ;
    SHAPE ABUTMENT ;
    PORT
      LAYER M3 ;
      RECT 61.263 180.522 61.281 180.576 ;
    END
  END rw0_rd_out[72]
  PIN rw0_rd_out[73]
    DIRECTION OUTPUT ;
    USE SIGNAL ;
    SHAPE ABUTMENT ;
    PORT
      LAYER M3 ;
      RECT 65.079 180.522 65.097 180.576 ;
    END
  END rw0_rd_out[73]
  PIN rw0_rd_out[74]
    DIRECTION OUTPUT ;
    USE SIGNAL ;
    SHAPE ABUTMENT ;
    PORT
      LAYER M3 ;
      RECT 68.895 180.522 68.913 180.576 ;
    END
  END rw0_rd_out[74]
  PIN rw0_rd_out[75]
    DIRECTION OUTPUT ;
    USE SIGNAL ;
    SHAPE ABUTMENT ;
    PORT
      LAYER M3 ;
      RECT 72.711 180.522 72.729 180.576 ;
    END
  END rw0_rd_out[75]
  PIN rw0_rd_out[76]
    DIRECTION OUTPUT ;
    USE SIGNAL ;
    SHAPE ABUTMENT ;
    PORT
      LAYER M3 ;
      RECT 76.527 180.522 76.545 180.576 ;
    END
  END rw0_rd_out[76]
  PIN rw0_rd_out[77]
    DIRECTION OUTPUT ;
    USE SIGNAL ;
    SHAPE ABUTMENT ;
    PORT
      LAYER M3 ;
      RECT 80.343 180.522 80.361 180.576 ;
    END
  END rw0_rd_out[77]
  PIN rw0_rd_out[78]
    DIRECTION OUTPUT ;
    USE SIGNAL ;
    SHAPE ABUTMENT ;
    PORT
      LAYER M3 ;
      RECT 84.159 180.522 84.177 180.576 ;
    END
  END rw0_rd_out[78]
  PIN rw0_rd_out[79]
    DIRECTION OUTPUT ;
    USE SIGNAL ;
    SHAPE ABUTMENT ;
    PORT
      LAYER M3 ;
      RECT 87.975 180.522 87.993 180.576 ;
    END
  END rw0_rd_out[79]
  PIN rw0_rd_out[80]
    DIRECTION OUTPUT ;
    USE SIGNAL ;
    SHAPE ABUTMENT ;
    PORT
      LAYER M3 ;
      RECT 91.791 180.522 91.809 180.576 ;
    END
  END rw0_rd_out[80]
  PIN rw0_rd_out[81]
    DIRECTION OUTPUT ;
    USE SIGNAL ;
    SHAPE ABUTMENT ;
    PORT
      LAYER M3 ;
      RECT 95.607 180.522 95.625 180.576 ;
    END
  END rw0_rd_out[81]
  PIN rw0_rd_out[82]
    DIRECTION OUTPUT ;
    USE SIGNAL ;
    SHAPE ABUTMENT ;
    PORT
      LAYER M3 ;
      RECT 99.423 180.522 99.441 180.576 ;
    END
  END rw0_rd_out[82]
  PIN rw0_rd_out[83]
    DIRECTION OUTPUT ;
    USE SIGNAL ;
    SHAPE ABUTMENT ;
    PORT
      LAYER M3 ;
      RECT 103.239 180.522 103.257 180.576 ;
    END
  END rw0_rd_out[83]
  PIN rw0_rd_out[84]
    DIRECTION OUTPUT ;
    USE SIGNAL ;
    SHAPE ABUTMENT ;
    PORT
      LAYER M3 ;
      RECT 107.055 180.522 107.073 180.576 ;
    END
  END rw0_rd_out[84]
  PIN rw0_rd_out[85]
    DIRECTION OUTPUT ;
    USE SIGNAL ;
    SHAPE ABUTMENT ;
    PORT
      LAYER M3 ;
      RECT 110.871 180.522 110.889 180.576 ;
    END
  END rw0_rd_out[85]
  PIN rw0_rd_out[86]
    DIRECTION OUTPUT ;
    USE SIGNAL ;
    SHAPE ABUTMENT ;
    PORT
      LAYER M3 ;
      RECT 114.687 180.522 114.705 180.576 ;
    END
  END rw0_rd_out[86]
  PIN rw0_rd_out[87]
    DIRECTION OUTPUT ;
    USE SIGNAL ;
    SHAPE ABUTMENT ;
    PORT
      LAYER M3 ;
      RECT 118.503 180.522 118.521 180.576 ;
    END
  END rw0_rd_out[87]
  PIN rw0_rd_out[88]
    DIRECTION OUTPUT ;
    USE SIGNAL ;
    SHAPE ABUTMENT ;
    PORT
      LAYER M3 ;
      RECT 122.319 180.522 122.337 180.576 ;
    END
  END rw0_rd_out[88]
  PIN rw0_rd_out[89]
    DIRECTION OUTPUT ;
    USE SIGNAL ;
    SHAPE ABUTMENT ;
    PORT
      LAYER M3 ;
      RECT 126.135 180.522 126.153 180.576 ;
    END
  END rw0_rd_out[89]
  PIN rw0_rd_out[90]
    DIRECTION OUTPUT ;
    USE SIGNAL ;
    SHAPE ABUTMENT ;
    PORT
      LAYER M3 ;
      RECT 129.951 180.522 129.969 180.576 ;
    END
  END rw0_rd_out[90]
  PIN rw0_rd_out[91]
    DIRECTION OUTPUT ;
    USE SIGNAL ;
    SHAPE ABUTMENT ;
    PORT
      LAYER M3 ;
      RECT 133.767 180.522 133.785 180.576 ;
    END
  END rw0_rd_out[91]
  PIN rw0_rd_out[92]
    DIRECTION OUTPUT ;
    USE SIGNAL ;
    SHAPE ABUTMENT ;
    PORT
      LAYER M3 ;
      RECT 137.583 180.522 137.601 180.576 ;
    END
  END rw0_rd_out[92]
  PIN rw0_rd_out[93]
    DIRECTION OUTPUT ;
    USE SIGNAL ;
    SHAPE ABUTMENT ;
    PORT
      LAYER M3 ;
      RECT 141.399 180.522 141.417 180.576 ;
    END
  END rw0_rd_out[93]
  PIN rw0_rd_out[94]
    DIRECTION OUTPUT ;
    USE SIGNAL ;
    SHAPE ABUTMENT ;
    PORT
      LAYER M3 ;
      RECT 145.215 180.522 145.233 180.576 ;
    END
  END rw0_rd_out[94]
  PIN rw0_rd_out[95]
    DIRECTION OUTPUT ;
    USE SIGNAL ;
    SHAPE ABUTMENT ;
    PORT
      LAYER M3 ;
      RECT 149.031 180.522 149.049 180.576 ;
    END
  END rw0_rd_out[95]
  PIN rw0_rd_out[96]
    DIRECTION OUTPUT ;
    USE SIGNAL ;
    SHAPE ABUTMENT ;
    PORT
      LAYER M3 ;
      RECT 152.847 180.522 152.865 180.576 ;
    END
  END rw0_rd_out[96]
  PIN rw0_rd_out[97]
    DIRECTION OUTPUT ;
    USE SIGNAL ;
    SHAPE ABUTMENT ;
    PORT
      LAYER M3 ;
      RECT 156.663 180.522 156.681 180.576 ;
    END
  END rw0_rd_out[97]
  PIN rw0_rd_out[98]
    DIRECTION OUTPUT ;
    USE SIGNAL ;
    SHAPE ABUTMENT ;
    PORT
      LAYER M3 ;
      RECT 160.479 180.522 160.497 180.576 ;
    END
  END rw0_rd_out[98]
  PIN rw0_rd_out[99]
    DIRECTION OUTPUT ;
    USE SIGNAL ;
    SHAPE ABUTMENT ;
    PORT
      LAYER M3 ;
      RECT 164.295 180.522 164.313 180.576 ;
    END
  END rw0_rd_out[99]
  PIN rw0_rd_out[100]
    DIRECTION OUTPUT ;
    USE SIGNAL ;
    SHAPE ABUTMENT ;
    PORT
      LAYER M3 ;
      RECT 168.111 180.522 168.129 180.576 ;
    END
  END rw0_rd_out[100]
  PIN rw0_rd_out[101]
    DIRECTION OUTPUT ;
    USE SIGNAL ;
    SHAPE ABUTMENT ;
    PORT
      LAYER M3 ;
      RECT 171.927 180.522 171.945 180.576 ;
    END
  END rw0_rd_out[101]
  PIN rw0_rd_out[102]
    DIRECTION OUTPUT ;
    USE SIGNAL ;
    SHAPE ABUTMENT ;
    PORT
      LAYER M3 ;
      RECT 175.743 180.522 175.761 180.576 ;
    END
  END rw0_rd_out[102]
  PIN rw0_rd_out[103]
    DIRECTION OUTPUT ;
    USE SIGNAL ;
    SHAPE ABUTMENT ;
    PORT
      LAYER M3 ;
      RECT 179.559 180.522 179.577 180.576 ;
    END
  END rw0_rd_out[103]
  PIN rw0_rd_out[104]
    DIRECTION OUTPUT ;
    USE SIGNAL ;
    SHAPE ABUTMENT ;
    PORT
      LAYER M3 ;
      RECT 183.375 180.522 183.393 180.576 ;
    END
  END rw0_rd_out[104]
  PIN rw0_rd_out[105]
    DIRECTION OUTPUT ;
    USE SIGNAL ;
    SHAPE ABUTMENT ;
    PORT
      LAYER M3 ;
      RECT 187.191 180.522 187.209 180.576 ;
    END
  END rw0_rd_out[105]
  PIN rw0_rd_out[106]
    DIRECTION OUTPUT ;
    USE SIGNAL ;
    SHAPE ABUTMENT ;
    PORT
      LAYER M3 ;
      RECT 191.007 180.522 191.025 180.576 ;
    END
  END rw0_rd_out[106]
  PIN rw0_rd_out[107]
    DIRECTION OUTPUT ;
    USE SIGNAL ;
    SHAPE ABUTMENT ;
    PORT
      LAYER M3 ;
      RECT 194.823 180.522 194.841 180.576 ;
    END
  END rw0_rd_out[107]
  PIN rw0_rd_out[108]
    DIRECTION OUTPUT ;
    USE SIGNAL ;
    SHAPE ABUTMENT ;
    PORT
      LAYER M3 ;
      RECT 198.639 180.522 198.657 180.576 ;
    END
  END rw0_rd_out[108]
  PIN rw0_rd_out[109]
    DIRECTION OUTPUT ;
    USE SIGNAL ;
    SHAPE ABUTMENT ;
    PORT
      LAYER M3 ;
      RECT 202.455 180.522 202.473 180.576 ;
    END
  END rw0_rd_out[109]
  PIN rw0_rd_out[110]
    DIRECTION OUTPUT ;
    USE SIGNAL ;
    SHAPE ABUTMENT ;
    PORT
      LAYER M3 ;
      RECT 206.271 180.522 206.289 180.576 ;
    END
  END rw0_rd_out[110]
  PIN rw0_rd_out[111]
    DIRECTION OUTPUT ;
    USE SIGNAL ;
    SHAPE ABUTMENT ;
    PORT
      LAYER M3 ;
      RECT 210.087 180.522 210.105 180.576 ;
    END
  END rw0_rd_out[111]
  PIN rw0_rd_out[112]
    DIRECTION OUTPUT ;
    USE SIGNAL ;
    SHAPE ABUTMENT ;
    PORT
      LAYER M3 ;
      RECT 213.903 180.522 213.921 180.576 ;
    END
  END rw0_rd_out[112]
  PIN rw0_rd_out[113]
    DIRECTION OUTPUT ;
    USE SIGNAL ;
    SHAPE ABUTMENT ;
    PORT
      LAYER M3 ;
      RECT 217.719 180.522 217.737 180.576 ;
    END
  END rw0_rd_out[113]
  PIN rw0_rd_out[114]
    DIRECTION OUTPUT ;
    USE SIGNAL ;
    SHAPE ABUTMENT ;
    PORT
      LAYER M3 ;
      RECT 221.535 180.522 221.553 180.576 ;
    END
  END rw0_rd_out[114]
  PIN rw0_rd_out[115]
    DIRECTION OUTPUT ;
    USE SIGNAL ;
    SHAPE ABUTMENT ;
    PORT
      LAYER M3 ;
      RECT 225.351 180.522 225.369 180.576 ;
    END
  END rw0_rd_out[115]
  PIN rw0_rd_out[116]
    DIRECTION OUTPUT ;
    USE SIGNAL ;
    SHAPE ABUTMENT ;
    PORT
      LAYER M3 ;
      RECT 229.167 180.522 229.185 180.576 ;
    END
  END rw0_rd_out[116]
  PIN rw0_rd_out[117]
    DIRECTION OUTPUT ;
    USE SIGNAL ;
    SHAPE ABUTMENT ;
    PORT
      LAYER M3 ;
      RECT 232.983 180.522 233.001 180.576 ;
    END
  END rw0_rd_out[117]
  PIN rw0_rd_out[118]
    DIRECTION OUTPUT ;
    USE SIGNAL ;
    SHAPE ABUTMENT ;
    PORT
      LAYER M3 ;
      RECT 236.799 180.522 236.817 180.576 ;
    END
  END rw0_rd_out[118]
  PIN rw0_rd_out[119]
    DIRECTION OUTPUT ;
    USE SIGNAL ;
    SHAPE ABUTMENT ;
    PORT
      LAYER M3 ;
      RECT 240.615 180.522 240.633 180.576 ;
    END
  END rw0_rd_out[119]
  PIN rw0_rd_out[120]
    DIRECTION OUTPUT ;
    USE SIGNAL ;
    SHAPE ABUTMENT ;
    PORT
      LAYER M3 ;
      RECT 244.431 180.522 244.449 180.576 ;
    END
  END rw0_rd_out[120]
  PIN rw0_rd_out[121]
    DIRECTION OUTPUT ;
    USE SIGNAL ;
    SHAPE ABUTMENT ;
    PORT
      LAYER M3 ;
      RECT 248.247 180.522 248.265 180.576 ;
    END
  END rw0_rd_out[121]
  PIN rw0_rd_out[122]
    DIRECTION OUTPUT ;
    USE SIGNAL ;
    SHAPE ABUTMENT ;
    PORT
      LAYER M3 ;
      RECT 252.063 180.522 252.081 180.576 ;
    END
  END rw0_rd_out[122]
  PIN rw0_rd_out[123]
    DIRECTION OUTPUT ;
    USE SIGNAL ;
    SHAPE ABUTMENT ;
    PORT
      LAYER M3 ;
      RECT 255.879 180.522 255.897 180.576 ;
    END
  END rw0_rd_out[123]
  PIN rw0_rd_out[124]
    DIRECTION OUTPUT ;
    USE SIGNAL ;
    SHAPE ABUTMENT ;
    PORT
      LAYER M3 ;
      RECT 259.695 180.522 259.713 180.576 ;
    END
  END rw0_rd_out[124]
  PIN rw0_rd_out[125]
    DIRECTION OUTPUT ;
    USE SIGNAL ;
    SHAPE ABUTMENT ;
    PORT
      LAYER M3 ;
      RECT 263.511 180.522 263.529 180.576 ;
    END
  END rw0_rd_out[125]
  PIN rw0_rd_out[126]
    DIRECTION OUTPUT ;
    USE SIGNAL ;
    SHAPE ABUTMENT ;
    PORT
      LAYER M3 ;
      RECT 267.327 180.522 267.345 180.576 ;
    END
  END rw0_rd_out[126]
  PIN rw0_rd_out[127]
    DIRECTION OUTPUT ;
    USE SIGNAL ;
    SHAPE ABUTMENT ;
    PORT
      LAYER M3 ;
      RECT 271.143 180.522 271.161 180.576 ;
    END
  END rw0_rd_out[127]
  PIN rw0_addr_in[0]
    DIRECTION INPUT ;
    USE SIGNAL ;
    SHAPE ABUTMENT ;
    PORT
      LAYER M4 ;
      RECT 0.000 154.068 0.072 154.092 ;
    END
  END rw0_addr_in[0]
  PIN rw0_addr_in[1]
    DIRECTION INPUT ;
    USE SIGNAL ;
    SHAPE ABUTMENT ;
    PORT
      LAYER M4 ;
      RECT 0.000 158.340 0.072 158.364 ;
    END
  END rw0_addr_in[1]
  PIN rw0_addr_in[2]
    DIRECTION INPUT ;
    USE SIGNAL ;
    SHAPE ABUTMENT ;
    PORT
      LAYER M4 ;
      RECT 0.000 162.612 0.072 162.636 ;
    END
  END rw0_addr_in[2]
  PIN rw0_addr_in[3]
    DIRECTION INPUT ;
    USE SIGNAL ;
    SHAPE ABUTMENT ;
    PORT
      LAYER M4 ;
      RECT 0.000 166.884 0.072 166.908 ;
    END
  END rw0_addr_in[3]
  PIN rw0_addr_in[4]
    DIRECTION INPUT ;
    USE SIGNAL ;
    SHAPE ABUTMENT ;
    PORT
      LAYER M4 ;
      RECT 0.000 171.156 0.072 171.180 ;
    END
  END rw0_addr_in[4]
  PIN rw0_addr_in[5]
    DIRECTION INPUT ;
    USE SIGNAL ;
    SHAPE ABUTMENT ;
    PORT
      LAYER M4 ;
      RECT 0.000 175.428 0.072 175.452 ;
    END
  END rw0_addr_in[5]
  PIN rw0_addr_in[6]
    DIRECTION INPUT ;
    USE SIGNAL ;
    SHAPE ABUTMENT ;
    PORT
      LAYER M4 ;
      RECT 288.850 154.068 288.922 154.092 ;
    END
  END rw0_addr_in[6]
  PIN rw0_addr_in[7]
    DIRECTION INPUT ;
    USE SIGNAL ;
    SHAPE ABUTMENT ;
    PORT
      LAYER M4 ;
      RECT 288.850 158.340 288.922 158.364 ;
    END
  END rw0_addr_in[7]
  PIN rw0_addr_in[8]
    DIRECTION INPUT ;
    USE SIGNAL ;
    SHAPE ABUTMENT ;
    PORT
      LAYER M4 ;
      RECT 288.850 162.612 288.922 162.636 ;
    END
  END rw0_addr_in[8]
  PIN rw0_addr_in[9]
    DIRECTION INPUT ;
    USE SIGNAL ;
    SHAPE ABUTMENT ;
    PORT
      LAYER M4 ;
      RECT 288.850 166.884 288.922 166.908 ;
    END
  END rw0_addr_in[9]
  PIN rw0_addr_in[10]
    DIRECTION INPUT ;
    USE SIGNAL ;
    SHAPE ABUTMENT ;
    PORT
      LAYER M4 ;
      RECT 288.850 171.156 288.922 171.180 ;
    END
  END rw0_addr_in[10]
  PIN rw0_we_in
    DIRECTION INPUT ;
    USE SIGNAL ;
    SHAPE ABUTMENT ;
    PORT
      LAYER M3 ;
      RECT 274.959 180.522 274.977 180.576 ;
    END
  END rw0_we_in
  PIN rw0_ce_in
    DIRECTION INPUT ;
    USE SIGNAL ;
    SHAPE ABUTMENT ;
    PORT
      LAYER M3 ;
      RECT 278.775 180.522 278.793 180.576 ;
    END
  END rw0_ce_in
  PIN rw0_clk
    DIRECTION INPUT ;
    USE SIGNAL ;
    SHAPE ABUTMENT ;
    PORT
      LAYER M3 ;
      RECT 282.591 180.522 282.609 180.576 ;
    END
  END rw0_clk
  PIN VSS
    DIRECTION INOUT ;
    USE GROUND ;
    PORT
      LAYER M4 ;
      RECT 0.216 0.240 288.706 0.336 ;
      RECT 0.216 1.008 288.706 1.104 ;
      RECT 0.216 1.776 288.706 1.872 ;
      RECT 0.216 2.544 288.706 2.640 ;
      RECT 0.216 3.312 288.706 3.408 ;
      RECT 0.216 4.080 288.706 4.176 ;
      RECT 0.216 4.848 288.706 4.944 ;
      RECT 0.216 5.616 288.706 5.712 ;
      RECT 0.216 6.384 288.706 6.480 ;
      RECT 0.216 7.152 288.706 7.248 ;
      RECT 0.216 7.920 288.706 8.016 ;
      RECT 0.216 8.688 288.706 8.784 ;
      RECT 0.216 9.456 288.706 9.552 ;
      RECT 0.216 10.224 288.706 10.320 ;
      RECT 0.216 10.992 288.706 11.088 ;
      RECT 0.216 11.760 288.706 11.856 ;
      RECT 0.216 12.528 288.706 12.624 ;
      RECT 0.216 13.296 288.706 13.392 ;
      RECT 0.216 14.064 288.706 14.160 ;
      RECT 0.216 14.832 288.706 14.928 ;
      RECT 0.216 15.600 288.706 15.696 ;
      RECT 0.216 16.368 288.706 16.464 ;
      RECT 0.216 17.136 288.706 17.232 ;
      RECT 0.216 17.904 288.706 18.000 ;
      RECT 0.216 18.672 288.706 18.768 ;
      RECT 0.216 19.440 288.706 19.536 ;
      RECT 0.216 20.208 288.706 20.304 ;
      RECT 0.216 20.976 288.706 21.072 ;
      RECT 0.216 21.744 288.706 21.840 ;
      RECT 0.216 22.512 288.706 22.608 ;
      RECT 0.216 23.280 288.706 23.376 ;
      RECT 0.216 24.048 288.706 24.144 ;
      RECT 0.216 24.816 288.706 24.912 ;
      RECT 0.216 25.584 288.706 25.680 ;
      RECT 0.216 26.352 288.706 26.448 ;
      RECT 0.216 27.120 288.706 27.216 ;
      RECT 0.216 27.888 288.706 27.984 ;
      RECT 0.216 28.656 288.706 28.752 ;
      RECT 0.216 29.424 288.706 29.520 ;
      RECT 0.216 30.192 288.706 30.288 ;
      RECT 0.216 30.960 288.706 31.056 ;
      RECT 0.216 31.728 288.706 31.824 ;
      RECT 0.216 32.496 288.706 32.592 ;
      RECT 0.216 33.264 288.706 33.360 ;
      RECT 0.216 34.032 288.706 34.128 ;
      RECT 0.216 34.800 288.706 34.896 ;
      RECT 0.216 35.568 288.706 35.664 ;
      RECT 0.216 36.336 288.706 36.432 ;
      RECT 0.216 37.104 288.706 37.200 ;
      RECT 0.216 37.872 288.706 37.968 ;
      RECT 0.216 38.640 288.706 38.736 ;
      RECT 0.216 39.408 288.706 39.504 ;
      RECT 0.216 40.176 288.706 40.272 ;
      RECT 0.216 40.944 288.706 41.040 ;
      RECT 0.216 41.712 288.706 41.808 ;
      RECT 0.216 42.480 288.706 42.576 ;
      RECT 0.216 43.248 288.706 43.344 ;
      RECT 0.216 44.016 288.706 44.112 ;
      RECT 0.216 44.784 288.706 44.880 ;
      RECT 0.216 45.552 288.706 45.648 ;
      RECT 0.216 46.320 288.706 46.416 ;
      RECT 0.216 47.088 288.706 47.184 ;
      RECT 0.216 47.856 288.706 47.952 ;
      RECT 0.216 48.624 288.706 48.720 ;
      RECT 0.216 49.392 288.706 49.488 ;
      RECT 0.216 50.160 288.706 50.256 ;
      RECT 0.216 50.928 288.706 51.024 ;
      RECT 0.216 51.696 288.706 51.792 ;
      RECT 0.216 52.464 288.706 52.560 ;
      RECT 0.216 53.232 288.706 53.328 ;
      RECT 0.216 54.000 288.706 54.096 ;
      RECT 0.216 54.768 288.706 54.864 ;
      RECT 0.216 55.536 288.706 55.632 ;
      RECT 0.216 56.304 288.706 56.400 ;
      RECT 0.216 57.072 288.706 57.168 ;
      RECT 0.216 57.840 288.706 57.936 ;
      RECT 0.216 58.608 288.706 58.704 ;
      RECT 0.216 59.376 288.706 59.472 ;
      RECT 0.216 60.144 288.706 60.240 ;
      RECT 0.216 60.912 288.706 61.008 ;
      RECT 0.216 61.680 288.706 61.776 ;
      RECT 0.216 62.448 288.706 62.544 ;
      RECT 0.216 63.216 288.706 63.312 ;
      RECT 0.216 63.984 288.706 64.080 ;
      RECT 0.216 64.752 288.706 64.848 ;
      RECT 0.216 65.520 288.706 65.616 ;
      RECT 0.216 66.288 288.706 66.384 ;
      RECT 0.216 67.056 288.706 67.152 ;
      RECT 0.216 67.824 288.706 67.920 ;
      RECT 0.216 68.592 288.706 68.688 ;
      RECT 0.216 69.360 288.706 69.456 ;
      RECT 0.216 70.128 288.706 70.224 ;
      RECT 0.216 70.896 288.706 70.992 ;
      RECT 0.216 71.664 288.706 71.760 ;
      RECT 0.216 72.432 288.706 72.528 ;
      RECT 0.216 73.200 288.706 73.296 ;
      RECT 0.216 73.968 288.706 74.064 ;
      RECT 0.216 74.736 288.706 74.832 ;
      RECT 0.216 75.504 288.706 75.600 ;
      RECT 0.216 76.272 288.706 76.368 ;
      RECT 0.216 77.040 288.706 77.136 ;
      RECT 0.216 77.808 288.706 77.904 ;
      RECT 0.216 78.576 288.706 78.672 ;
      RECT 0.216 79.344 288.706 79.440 ;
      RECT 0.216 80.112 288.706 80.208 ;
      RECT 0.216 80.880 288.706 80.976 ;
      RECT 0.216 81.648 288.706 81.744 ;
      RECT 0.216 82.416 288.706 82.512 ;
      RECT 0.216 83.184 288.706 83.280 ;
      RECT 0.216 83.952 288.706 84.048 ;
      RECT 0.216 84.720 288.706 84.816 ;
      RECT 0.216 85.488 288.706 85.584 ;
      RECT 0.216 86.256 288.706 86.352 ;
      RECT 0.216 87.024 288.706 87.120 ;
      RECT 0.216 87.792 288.706 87.888 ;
      RECT 0.216 88.560 288.706 88.656 ;
      RECT 0.216 89.328 288.706 89.424 ;
      RECT 0.216 90.096 288.706 90.192 ;
      RECT 0.216 90.864 288.706 90.960 ;
      RECT 0.216 91.632 288.706 91.728 ;
      RECT 0.216 92.400 288.706 92.496 ;
      RECT 0.216 93.168 288.706 93.264 ;
      RECT 0.216 93.936 288.706 94.032 ;
      RECT 0.216 94.704 288.706 94.800 ;
      RECT 0.216 95.472 288.706 95.568 ;
      RECT 0.216 96.240 288.706 96.336 ;
      RECT 0.216 97.008 288.706 97.104 ;
      RECT 0.216 97.776 288.706 97.872 ;
      RECT 0.216 98.544 288.706 98.640 ;
      RECT 0.216 99.312 288.706 99.408 ;
      RECT 0.216 100.080 288.706 100.176 ;
      RECT 0.216 100.848 288.706 100.944 ;
      RECT 0.216 101.616 288.706 101.712 ;
      RECT 0.216 102.384 288.706 102.480 ;
      RECT 0.216 103.152 288.706 103.248 ;
      RECT 0.216 103.920 288.706 104.016 ;
      RECT 0.216 104.688 288.706 104.784 ;
      RECT 0.216 105.456 288.706 105.552 ;
      RECT 0.216 106.224 288.706 106.320 ;
      RECT 0.216 106.992 288.706 107.088 ;
      RECT 0.216 107.760 288.706 107.856 ;
      RECT 0.216 108.528 288.706 108.624 ;
      RECT 0.216 109.296 288.706 109.392 ;
      RECT 0.216 110.064 288.706 110.160 ;
      RECT 0.216 110.832 288.706 110.928 ;
      RECT 0.216 111.600 288.706 111.696 ;
      RECT 0.216 112.368 288.706 112.464 ;
      RECT 0.216 113.136 288.706 113.232 ;
      RECT 0.216 113.904 288.706 114.000 ;
      RECT 0.216 114.672 288.706 114.768 ;
      RECT 0.216 115.440 288.706 115.536 ;
      RECT 0.216 116.208 288.706 116.304 ;
      RECT 0.216 116.976 288.706 117.072 ;
      RECT 0.216 117.744 288.706 117.840 ;
      RECT 0.216 118.512 288.706 118.608 ;
      RECT 0.216 119.280 288.706 119.376 ;
      RECT 0.216 120.048 288.706 120.144 ;
      RECT 0.216 120.816 288.706 120.912 ;
      RECT 0.216 121.584 288.706 121.680 ;
      RECT 0.216 122.352 288.706 122.448 ;
      RECT 0.216 123.120 288.706 123.216 ;
      RECT 0.216 123.888 288.706 123.984 ;
      RECT 0.216 124.656 288.706 124.752 ;
      RECT 0.216 125.424 288.706 125.520 ;
      RECT 0.216 126.192 288.706 126.288 ;
      RECT 0.216 126.960 288.706 127.056 ;
      RECT 0.216 127.728 288.706 127.824 ;
      RECT 0.216 128.496 288.706 128.592 ;
      RECT 0.216 129.264 288.706 129.360 ;
      RECT 0.216 130.032 288.706 130.128 ;
      RECT 0.216 130.800 288.706 130.896 ;
      RECT 0.216 131.568 288.706 131.664 ;
      RECT 0.216 132.336 288.706 132.432 ;
      RECT 0.216 133.104 288.706 133.200 ;
      RECT 0.216 133.872 288.706 133.968 ;
      RECT 0.216 134.640 288.706 134.736 ;
      RECT 0.216 135.408 288.706 135.504 ;
      RECT 0.216 136.176 288.706 136.272 ;
      RECT 0.216 136.944 288.706 137.040 ;
      RECT 0.216 137.712 288.706 137.808 ;
      RECT 0.216 138.480 288.706 138.576 ;
      RECT 0.216 139.248 288.706 139.344 ;
      RECT 0.216 140.016 288.706 140.112 ;
      RECT 0.216 140.784 288.706 140.880 ;
      RECT 0.216 141.552 288.706 141.648 ;
      RECT 0.216 142.320 288.706 142.416 ;
      RECT 0.216 143.088 288.706 143.184 ;
      RECT 0.216 143.856 288.706 143.952 ;
      RECT 0.216 144.624 288.706 144.720 ;
      RECT 0.216 145.392 288.706 145.488 ;
      RECT 0.216 146.160 288.706 146.256 ;
      RECT 0.216 146.928 288.706 147.024 ;
      RECT 0.216 147.696 288.706 147.792 ;
      RECT 0.216 148.464 288.706 148.560 ;
      RECT 0.216 149.232 288.706 149.328 ;
      RECT 0.216 150.000 288.706 150.096 ;
      RECT 0.216 150.768 288.706 150.864 ;
      RECT 0.216 151.536 288.706 151.632 ;
      RECT 0.216 152.304 288.706 152.400 ;
      RECT 0.216 153.072 288.706 153.168 ;
      RECT 0.216 153.840 288.706 153.936 ;
      RECT 0.216 154.608 288.706 154.704 ;
      RECT 0.216 155.376 288.706 155.472 ;
      RECT 0.216 156.144 288.706 156.240 ;
      RECT 0.216 156.912 288.706 157.008 ;
      RECT 0.216 157.680 288.706 157.776 ;
      RECT 0.216 158.448 288.706 158.544 ;
      RECT 0.216 159.216 288.706 159.312 ;
      RECT 0.216 159.984 288.706 160.080 ;
      RECT 0.216 160.752 288.706 160.848 ;
      RECT 0.216 161.520 288.706 161.616 ;
      RECT 0.216 162.288 288.706 162.384 ;
      RECT 0.216 163.056 288.706 163.152 ;
      RECT 0.216 163.824 288.706 163.920 ;
      RECT 0.216 164.592 288.706 164.688 ;
      RECT 0.216 165.360 288.706 165.456 ;
      RECT 0.216 166.128 288.706 166.224 ;
      RECT 0.216 166.896 288.706 166.992 ;
      RECT 0.216 167.664 288.706 167.760 ;
      RECT 0.216 168.432 288.706 168.528 ;
      RECT 0.216 169.200 288.706 169.296 ;
      RECT 0.216 169.968 288.706 170.064 ;
      RECT 0.216 170.736 288.706 170.832 ;
      RECT 0.216 171.504 288.706 171.600 ;
      RECT 0.216 172.272 288.706 172.368 ;
      RECT 0.216 173.040 288.706 173.136 ;
      RECT 0.216 173.808 288.706 173.904 ;
      RECT 0.216 174.576 288.706 174.672 ;
      RECT 0.216 175.344 288.706 175.440 ;
      RECT 0.216 176.112 288.706 176.208 ;
      RECT 0.216 176.880 288.706 176.976 ;
      RECT 0.216 177.648 288.706 177.744 ;
      RECT 0.216 178.416 288.706 178.512 ;
      RECT 0.216 179.184 288.706 179.280 ;
      RECT 0.216 179.952 288.706 180.048 ;
    END
  END VSS
  PIN VDD
    DIRECTION INOUT ;
    USE POWER ;
    PORT
      LAYER M4 ;
      RECT 0.216 0.240 288.706 0.336 ;
      RECT 0.216 1.008 288.706 1.104 ;
      RECT 0.216 1.776 288.706 1.872 ;
      RECT 0.216 2.544 288.706 2.640 ;
      RECT 0.216 3.312 288.706 3.408 ;
      RECT 0.216 4.080 288.706 4.176 ;
      RECT 0.216 4.848 288.706 4.944 ;
      RECT 0.216 5.616 288.706 5.712 ;
      RECT 0.216 6.384 288.706 6.480 ;
      RECT 0.216 7.152 288.706 7.248 ;
      RECT 0.216 7.920 288.706 8.016 ;
      RECT 0.216 8.688 288.706 8.784 ;
      RECT 0.216 9.456 288.706 9.552 ;
      RECT 0.216 10.224 288.706 10.320 ;
      RECT 0.216 10.992 288.706 11.088 ;
      RECT 0.216 11.760 288.706 11.856 ;
      RECT 0.216 12.528 288.706 12.624 ;
      RECT 0.216 13.296 288.706 13.392 ;
      RECT 0.216 14.064 288.706 14.160 ;
      RECT 0.216 14.832 288.706 14.928 ;
      RECT 0.216 15.600 288.706 15.696 ;
      RECT 0.216 16.368 288.706 16.464 ;
      RECT 0.216 17.136 288.706 17.232 ;
      RECT 0.216 17.904 288.706 18.000 ;
      RECT 0.216 18.672 288.706 18.768 ;
      RECT 0.216 19.440 288.706 19.536 ;
      RECT 0.216 20.208 288.706 20.304 ;
      RECT 0.216 20.976 288.706 21.072 ;
      RECT 0.216 21.744 288.706 21.840 ;
      RECT 0.216 22.512 288.706 22.608 ;
      RECT 0.216 23.280 288.706 23.376 ;
      RECT 0.216 24.048 288.706 24.144 ;
      RECT 0.216 24.816 288.706 24.912 ;
      RECT 0.216 25.584 288.706 25.680 ;
      RECT 0.216 26.352 288.706 26.448 ;
      RECT 0.216 27.120 288.706 27.216 ;
      RECT 0.216 27.888 288.706 27.984 ;
      RECT 0.216 28.656 288.706 28.752 ;
      RECT 0.216 29.424 288.706 29.520 ;
      RECT 0.216 30.192 288.706 30.288 ;
      RECT 0.216 30.960 288.706 31.056 ;
      RECT 0.216 31.728 288.706 31.824 ;
      RECT 0.216 32.496 288.706 32.592 ;
      RECT 0.216 33.264 288.706 33.360 ;
      RECT 0.216 34.032 288.706 34.128 ;
      RECT 0.216 34.800 288.706 34.896 ;
      RECT 0.216 35.568 288.706 35.664 ;
      RECT 0.216 36.336 288.706 36.432 ;
      RECT 0.216 37.104 288.706 37.200 ;
      RECT 0.216 37.872 288.706 37.968 ;
      RECT 0.216 38.640 288.706 38.736 ;
      RECT 0.216 39.408 288.706 39.504 ;
      RECT 0.216 40.176 288.706 40.272 ;
      RECT 0.216 40.944 288.706 41.040 ;
      RECT 0.216 41.712 288.706 41.808 ;
      RECT 0.216 42.480 288.706 42.576 ;
      RECT 0.216 43.248 288.706 43.344 ;
      RECT 0.216 44.016 288.706 44.112 ;
      RECT 0.216 44.784 288.706 44.880 ;
      RECT 0.216 45.552 288.706 45.648 ;
      RECT 0.216 46.320 288.706 46.416 ;
      RECT 0.216 47.088 288.706 47.184 ;
      RECT 0.216 47.856 288.706 47.952 ;
      RECT 0.216 48.624 288.706 48.720 ;
      RECT 0.216 49.392 288.706 49.488 ;
      RECT 0.216 50.160 288.706 50.256 ;
      RECT 0.216 50.928 288.706 51.024 ;
      RECT 0.216 51.696 288.706 51.792 ;
      RECT 0.216 52.464 288.706 52.560 ;
      RECT 0.216 53.232 288.706 53.328 ;
      RECT 0.216 54.000 288.706 54.096 ;
      RECT 0.216 54.768 288.706 54.864 ;
      RECT 0.216 55.536 288.706 55.632 ;
      RECT 0.216 56.304 288.706 56.400 ;
      RECT 0.216 57.072 288.706 57.168 ;
      RECT 0.216 57.840 288.706 57.936 ;
      RECT 0.216 58.608 288.706 58.704 ;
      RECT 0.216 59.376 288.706 59.472 ;
      RECT 0.216 60.144 288.706 60.240 ;
      RECT 0.216 60.912 288.706 61.008 ;
      RECT 0.216 61.680 288.706 61.776 ;
      RECT 0.216 62.448 288.706 62.544 ;
      RECT 0.216 63.216 288.706 63.312 ;
      RECT 0.216 63.984 288.706 64.080 ;
      RECT 0.216 64.752 288.706 64.848 ;
      RECT 0.216 65.520 288.706 65.616 ;
      RECT 0.216 66.288 288.706 66.384 ;
      RECT 0.216 67.056 288.706 67.152 ;
      RECT 0.216 67.824 288.706 67.920 ;
      RECT 0.216 68.592 288.706 68.688 ;
      RECT 0.216 69.360 288.706 69.456 ;
      RECT 0.216 70.128 288.706 70.224 ;
      RECT 0.216 70.896 288.706 70.992 ;
      RECT 0.216 71.664 288.706 71.760 ;
      RECT 0.216 72.432 288.706 72.528 ;
      RECT 0.216 73.200 288.706 73.296 ;
      RECT 0.216 73.968 288.706 74.064 ;
      RECT 0.216 74.736 288.706 74.832 ;
      RECT 0.216 75.504 288.706 75.600 ;
      RECT 0.216 76.272 288.706 76.368 ;
      RECT 0.216 77.040 288.706 77.136 ;
      RECT 0.216 77.808 288.706 77.904 ;
      RECT 0.216 78.576 288.706 78.672 ;
      RECT 0.216 79.344 288.706 79.440 ;
      RECT 0.216 80.112 288.706 80.208 ;
      RECT 0.216 80.880 288.706 80.976 ;
      RECT 0.216 81.648 288.706 81.744 ;
      RECT 0.216 82.416 288.706 82.512 ;
      RECT 0.216 83.184 288.706 83.280 ;
      RECT 0.216 83.952 288.706 84.048 ;
      RECT 0.216 84.720 288.706 84.816 ;
      RECT 0.216 85.488 288.706 85.584 ;
      RECT 0.216 86.256 288.706 86.352 ;
      RECT 0.216 87.024 288.706 87.120 ;
      RECT 0.216 87.792 288.706 87.888 ;
      RECT 0.216 88.560 288.706 88.656 ;
      RECT 0.216 89.328 288.706 89.424 ;
      RECT 0.216 90.096 288.706 90.192 ;
      RECT 0.216 90.864 288.706 90.960 ;
      RECT 0.216 91.632 288.706 91.728 ;
      RECT 0.216 92.400 288.706 92.496 ;
      RECT 0.216 93.168 288.706 93.264 ;
      RECT 0.216 93.936 288.706 94.032 ;
      RECT 0.216 94.704 288.706 94.800 ;
      RECT 0.216 95.472 288.706 95.568 ;
      RECT 0.216 96.240 288.706 96.336 ;
      RECT 0.216 97.008 288.706 97.104 ;
      RECT 0.216 97.776 288.706 97.872 ;
      RECT 0.216 98.544 288.706 98.640 ;
      RECT 0.216 99.312 288.706 99.408 ;
      RECT 0.216 100.080 288.706 100.176 ;
      RECT 0.216 100.848 288.706 100.944 ;
      RECT 0.216 101.616 288.706 101.712 ;
      RECT 0.216 102.384 288.706 102.480 ;
      RECT 0.216 103.152 288.706 103.248 ;
      RECT 0.216 103.920 288.706 104.016 ;
      RECT 0.216 104.688 288.706 104.784 ;
      RECT 0.216 105.456 288.706 105.552 ;
      RECT 0.216 106.224 288.706 106.320 ;
      RECT 0.216 106.992 288.706 107.088 ;
      RECT 0.216 107.760 288.706 107.856 ;
      RECT 0.216 108.528 288.706 108.624 ;
      RECT 0.216 109.296 288.706 109.392 ;
      RECT 0.216 110.064 288.706 110.160 ;
      RECT 0.216 110.832 288.706 110.928 ;
      RECT 0.216 111.600 288.706 111.696 ;
      RECT 0.216 112.368 288.706 112.464 ;
      RECT 0.216 113.136 288.706 113.232 ;
      RECT 0.216 113.904 288.706 114.000 ;
      RECT 0.216 114.672 288.706 114.768 ;
      RECT 0.216 115.440 288.706 115.536 ;
      RECT 0.216 116.208 288.706 116.304 ;
      RECT 0.216 116.976 288.706 117.072 ;
      RECT 0.216 117.744 288.706 117.840 ;
      RECT 0.216 118.512 288.706 118.608 ;
      RECT 0.216 119.280 288.706 119.376 ;
      RECT 0.216 120.048 288.706 120.144 ;
      RECT 0.216 120.816 288.706 120.912 ;
      RECT 0.216 121.584 288.706 121.680 ;
      RECT 0.216 122.352 288.706 122.448 ;
      RECT 0.216 123.120 288.706 123.216 ;
      RECT 0.216 123.888 288.706 123.984 ;
      RECT 0.216 124.656 288.706 124.752 ;
      RECT 0.216 125.424 288.706 125.520 ;
      RECT 0.216 126.192 288.706 126.288 ;
      RECT 0.216 126.960 288.706 127.056 ;
      RECT 0.216 127.728 288.706 127.824 ;
      RECT 0.216 128.496 288.706 128.592 ;
      RECT 0.216 129.264 288.706 129.360 ;
      RECT 0.216 130.032 288.706 130.128 ;
      RECT 0.216 130.800 288.706 130.896 ;
      RECT 0.216 131.568 288.706 131.664 ;
      RECT 0.216 132.336 288.706 132.432 ;
      RECT 0.216 133.104 288.706 133.200 ;
      RECT 0.216 133.872 288.706 133.968 ;
      RECT 0.216 134.640 288.706 134.736 ;
      RECT 0.216 135.408 288.706 135.504 ;
      RECT 0.216 136.176 288.706 136.272 ;
      RECT 0.216 136.944 288.706 137.040 ;
      RECT 0.216 137.712 288.706 137.808 ;
      RECT 0.216 138.480 288.706 138.576 ;
      RECT 0.216 139.248 288.706 139.344 ;
      RECT 0.216 140.016 288.706 140.112 ;
      RECT 0.216 140.784 288.706 140.880 ;
      RECT 0.216 141.552 288.706 141.648 ;
      RECT 0.216 142.320 288.706 142.416 ;
      RECT 0.216 143.088 288.706 143.184 ;
      RECT 0.216 143.856 288.706 143.952 ;
      RECT 0.216 144.624 288.706 144.720 ;
      RECT 0.216 145.392 288.706 145.488 ;
      RECT 0.216 146.160 288.706 146.256 ;
      RECT 0.216 146.928 288.706 147.024 ;
      RECT 0.216 147.696 288.706 147.792 ;
      RECT 0.216 148.464 288.706 148.560 ;
      RECT 0.216 149.232 288.706 149.328 ;
      RECT 0.216 150.000 288.706 150.096 ;
      RECT 0.216 150.768 288.706 150.864 ;
      RECT 0.216 151.536 288.706 151.632 ;
      RECT 0.216 152.304 288.706 152.400 ;
      RECT 0.216 153.072 288.706 153.168 ;
      RECT 0.216 153.840 288.706 153.936 ;
      RECT 0.216 154.608 288.706 154.704 ;
      RECT 0.216 155.376 288.706 155.472 ;
      RECT 0.216 156.144 288.706 156.240 ;
      RECT 0.216 156.912 288.706 157.008 ;
      RECT 0.216 157.680 288.706 157.776 ;
      RECT 0.216 158.448 288.706 158.544 ;
      RECT 0.216 159.216 288.706 159.312 ;
      RECT 0.216 159.984 288.706 160.080 ;
      RECT 0.216 160.752 288.706 160.848 ;
      RECT 0.216 161.520 288.706 161.616 ;
      RECT 0.216 162.288 288.706 162.384 ;
      RECT 0.216 163.056 288.706 163.152 ;
      RECT 0.216 163.824 288.706 163.920 ;
      RECT 0.216 164.592 288.706 164.688 ;
      RECT 0.216 165.360 288.706 165.456 ;
      RECT 0.216 166.128 288.706 166.224 ;
      RECT 0.216 166.896 288.706 166.992 ;
      RECT 0.216 167.664 288.706 167.760 ;
      RECT 0.216 168.432 288.706 168.528 ;
      RECT 0.216 169.200 288.706 169.296 ;
      RECT 0.216 169.968 288.706 170.064 ;
      RECT 0.216 170.736 288.706 170.832 ;
      RECT 0.216 171.504 288.706 171.600 ;
      RECT 0.216 172.272 288.706 172.368 ;
      RECT 0.216 173.040 288.706 173.136 ;
      RECT 0.216 173.808 288.706 173.904 ;
      RECT 0.216 174.576 288.706 174.672 ;
      RECT 0.216 175.344 288.706 175.440 ;
      RECT 0.216 176.112 288.706 176.208 ;
      RECT 0.216 176.880 288.706 176.976 ;
      RECT 0.216 177.648 288.706 177.744 ;
      RECT 0.216 178.416 288.706 178.512 ;
      RECT 0.216 179.184 288.706 179.280 ;
      RECT 0.216 179.952 288.706 180.048 ;
    END
  END VDD
  OBS
    LAYER M1 ;
    RECT 0 0 288.922 180.576 ;
    LAYER M2 ;
    RECT 0 0 288.922 180.576 ;
    LAYER M3 ;
    RECT 0 0 288.922 180.576 ;
    LAYER M4 ;
    RECT 0 0 288.922 180.576 ;
  END
END fakeram_2048x128_1rw

END LIBRARY
